### Tool : gds2rh
### RedHawk Version : 19.1.7p1 RHEL6
### Vendor : Apache Design, Inc. A Subsidiary of ANSYS, Inc. 
### Date : Mar 02 2019, 00:03:14 

### Date generated : Wed Sep 14 16:23:46 2022
 
### Command : gds2rh /nfs/an/disks/an_mos_scratch01/mos/prod/runs/c224uhdlpsprf-ext-version-r1-0-1/r641701_00_00/r641701_00_00/avm/rv_avm/gds2rh_options_powerup.txt

VERSION 5.5 ;
NAMESCASESENSITIVE ON ;
DIVIDERCHAR "/" ;
BUSBITCHARS "[]" ;
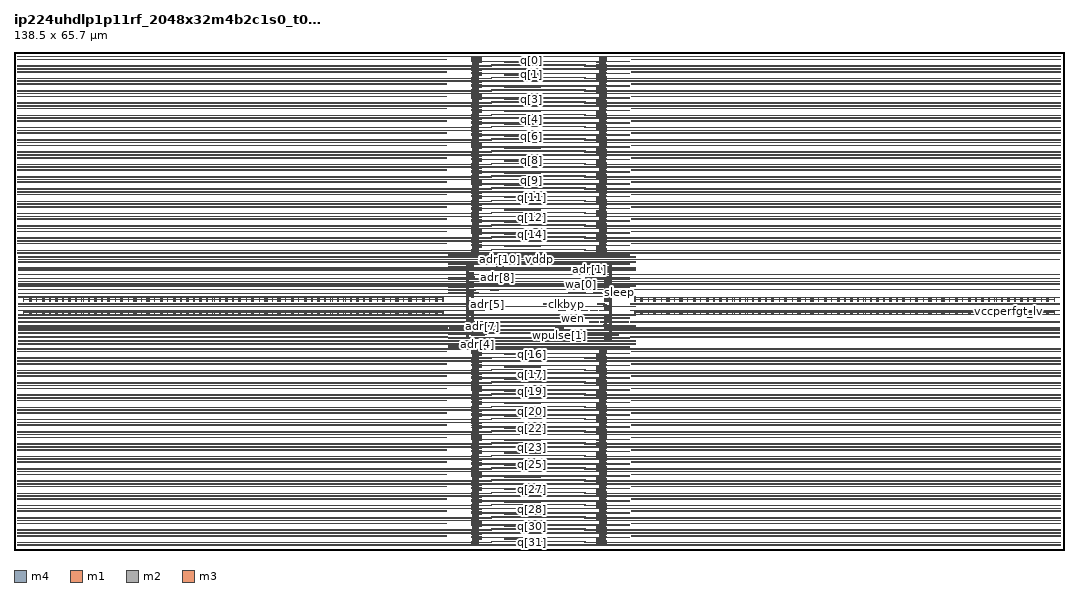
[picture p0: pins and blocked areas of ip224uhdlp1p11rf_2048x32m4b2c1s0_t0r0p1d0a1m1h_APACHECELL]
MACRO ip224uhdlp1p11rf_2048x32m4b2c1s0_t0r0p1d0a1m1h_APACHECELL
 ORIGIN 0.000000 0.000000 ;
 SIZE 138.500000 BY 65.700000 ;
 PIN adr[0]
 DIRECTION INPUT ;
 USE SIGNAL ;
 PORT
 LAYER m4 ;
 RECT 75.807500 37.004000 76.997500 37.080000 ;
 END
 END adr[0]
 PIN adr[10]
 DIRECTION INPUT ;
 USE SIGNAL ;
 PORT
 LAYER m4 ;
 RECT 63.625500 37.300000 64.577000 37.376000 ;
 END
 END adr[10]
 PIN adr[1]
 DIRECTION INPUT ;
 USE SIGNAL ;
 PORT
 LAYER m4 ;
 RECT 75.412500 35.884000 76.399500 35.960000 ;
 END
 END adr[1]
 PIN adr[2]
 DIRECTION INPUT ;
 USE SIGNAL ;
 PORT
 LAYER m4 ;
 RECT 75.238000 34.928000 76.412000 35.004000 ;
 END
 END adr[2]
 PIN adr[3]
 DIRECTION INPUT ;
 USE SIGNAL ;
 PORT
 LAYER m4 ;
 RECT 76.492000 34.928000 77.654000 35.004000 ;
 END
 END adr[3]
 PIN adr[4]
 DIRECTION INPUT ;
 USE SIGNAL ;
 PORT
 LAYER m4 ;
 RECT 60.693000 27.040000 61.650000 27.116000 ;
 END
 END adr[4]
 PIN adr[5]
 DIRECTION INPUT ;
 USE SIGNAL ;
 PORT
 LAYER m4 ;
 RECT 61.974500 32.406000 62.914000 32.462000 ;
 END
 END adr[5]
 PIN adr[6]
 DIRECTION INPUT ;
 USE SIGNAL ;
 PORT
 LAYER m4 ;
 RECT 60.656000 28.306000 62.037000 28.382000 ;
 END
 END adr[6]
 PIN adr[7]
 DIRECTION INPUT ;
 USE SIGNAL ;
 PORT
 LAYER m4 ;
 RECT 61.080500 28.456000 62.389000 28.532000 ;
 END
 END adr[7]
 PIN adr[8]
 DIRECTION INPUT ;
 USE SIGNAL ;
 PORT
 LAYER m4 ;
 RECT 63.343000 35.884000 64.267500 35.960000 ;
 END
 END adr[8]
 PIN adr[9]
 DIRECTION INPUT ;
 USE SIGNAL ;
 PORT
 LAYER m4 ;
 RECT 63.355000 37.004000 64.485000 37.080000 ;
 END
 END adr[9]
 PIN bc1
 DIRECTION INPUT ;
 USE SIGNAL ;
 PORT
 LAYER m4 ;
 RECT 75.492500 35.620000 76.556500 35.696000 ;
 END
 END bc1
 PIN bc2
 DIRECTION INPUT ;
 USE SIGNAL ;
 PORT
 LAYER m4 ;
 RECT 76.412000 33.938000 77.551500 33.994000 ;
 END
 END bc2
 PIN clkbyp
 DIRECTION INPUT ;
 USE SIGNAL ;
 PORT
 LAYER m4 ;
 RECT 72.415000 32.406000 73.267500 32.462000 ;
 END
 END clkbyp
 PIN deepslp
 DIRECTION INPUT ;
 USE SIGNAL ;
 PORT
 LAYER m4 ;
 RECT 76.916000 32.406000 77.910000 32.462000 ;
 END
 END deepslp
 PIN din[0]
 DIRECTION INPUT ;
 USE SIGNAL ;
 PORT
 LAYER m4 ;
 RECT 64.658000 64.268000 67.152500 64.376000 ;
 END
 END din[0]
 PIN din[10]
 DIRECTION INPUT ;
 USE SIGNAL ;
 PORT
 LAYER m4 ;
 RECT 64.658000 48.068000 67.152500 48.176000 ;
 END
 END din[10]
 PIN din[11]
 DIRECTION INPUT ;
 USE SIGNAL ;
 PORT
 LAYER m4 ;
 RECT 64.658000 46.448000 67.152500 46.556000 ;
 END
 END din[11]
 PIN din[12]
 DIRECTION INPUT ;
 USE SIGNAL ;
 PORT
 LAYER m4 ;
 RECT 64.658000 44.828000 67.152500 44.936000 ;
 END
 END din[12]
 PIN din[13]
 DIRECTION INPUT ;
 USE SIGNAL ;
 PORT
 LAYER m4 ;
 RECT 64.658000 43.208000 67.152500 43.316000 ;
 END
 END din[13]
 PIN din[14]
 DIRECTION INPUT ;
 USE SIGNAL ;
 PORT
 LAYER m4 ;
 RECT 64.658000 41.588000 67.152500 41.696000 ;
 END
 END din[14]
 PIN din[15]
 DIRECTION INPUT ;
 USE SIGNAL ;
 PORT
 LAYER m4 ;
 RECT 64.658000 39.968000 67.152500 40.076000 ;
 END
 END din[15]
 PIN din[16]
 DIRECTION INPUT ;
 USE SIGNAL ;
 PORT
 LAYER m4 ;
 RECT 64.658000 25.748000 67.152500 25.856000 ;
 END
 END din[16]
 PIN din[17]
 DIRECTION INPUT ;
 USE SIGNAL ;
 PORT
 LAYER m4 ;
 RECT 64.658000 24.128000 67.152500 24.236000 ;
 END
 END din[17]
 PIN din[18]
 DIRECTION INPUT ;
 USE SIGNAL ;
 PORT
 LAYER m4 ;
 RECT 64.658000 22.508000 67.152500 22.616000 ;
 END
 END din[18]
 PIN din[19]
 DIRECTION INPUT ;
 USE SIGNAL ;
 PORT
 LAYER m4 ;
 RECT 64.658000 20.888000 67.152500 20.996000 ;
 END
 END din[19]
 PIN din[1]
 DIRECTION INPUT ;
 USE SIGNAL ;
 PORT
 LAYER m4 ;
 RECT 64.658000 62.648000 67.152500 62.756000 ;
 END
 END din[1]
 PIN din[20]
 DIRECTION INPUT ;
 USE SIGNAL ;
 PORT
 LAYER m4 ;
 RECT 64.658000 19.268000 67.152500 19.376000 ;
 END
 END din[20]
 PIN din[21]
 DIRECTION INPUT ;
 USE SIGNAL ;
 PORT
 LAYER m4 ;
 RECT 64.658000 17.648000 67.152500 17.756000 ;
 END
 END din[21]
 PIN din[22]
 DIRECTION INPUT ;
 USE SIGNAL ;
 PORT
 LAYER m4 ;
 RECT 64.658000 16.028000 67.152500 16.136000 ;
 END
 END din[22]
 PIN din[23]
 DIRECTION INPUT ;
 USE SIGNAL ;
 PORT
 LAYER m4 ;
 RECT 64.658000 14.408000 67.152500 14.516000 ;
 END
 END din[23]
 PIN din[24]
 DIRECTION INPUT ;
 USE SIGNAL ;
 PORT
 LAYER m4 ;
 RECT 64.658000 12.788000 67.152500 12.896000 ;
 END
 END din[24]
 PIN din[25]
 DIRECTION INPUT ;
 USE SIGNAL ;
 PORT
 LAYER m4 ;
 RECT 64.658000 11.168000 67.152500 11.276000 ;
 END
 END din[25]
 PIN din[26]
 DIRECTION INPUT ;
 USE SIGNAL ;
 PORT
 LAYER m4 ;
 RECT 64.658000 9.548000 67.152500 9.656000 ;
 END
 END din[26]
 PIN din[27]
 DIRECTION INPUT ;
 USE SIGNAL ;
 PORT
 LAYER m4 ;
 RECT 64.658000 7.928000 67.152500 8.036000 ;
 END
 END din[27]
 PIN din[28]
 DIRECTION INPUT ;
 USE SIGNAL ;
 PORT
 LAYER m4 ;
 RECT 64.658000 6.308000 67.152500 6.416000 ;
 END
 END din[28]
 PIN din[29]
 DIRECTION INPUT ;
 USE SIGNAL ;
 PORT
 LAYER m4 ;
 RECT 64.658000 4.688000 67.152500 4.796000 ;
 END
 END din[29]
 PIN din[2]
 DIRECTION INPUT ;
 USE SIGNAL ;
 PORT
 LAYER m4 ;
 RECT 64.658000 61.028000 67.152500 61.136000 ;
 END
 END din[2]
 PIN din[30]
 DIRECTION INPUT ;
 USE SIGNAL ;
 PORT
 LAYER m4 ;
 RECT 64.658000 3.068000 67.152500 3.176000 ;
 END
 END din[30]
 PIN din[31]
 DIRECTION INPUT ;
 USE SIGNAL ;
 PORT
 LAYER m4 ;
 RECT 64.658000 1.448000 67.152500 1.556000 ;
 END
 END din[31]
 PIN din[3]
 DIRECTION INPUT ;
 USE SIGNAL ;
 PORT
 LAYER m4 ;
 RECT 64.658000 59.408000 67.152500 59.516000 ;
 END
 END din[3]
 PIN din[4]
 DIRECTION INPUT ;
 USE SIGNAL ;
 PORT
 LAYER m4 ;
 RECT 64.658000 57.788000 67.152500 57.896000 ;
 END
 END din[4]
 PIN din[5]
 DIRECTION INPUT ;
 USE SIGNAL ;
 PORT
 LAYER m4 ;
 RECT 64.658000 56.168000 67.152500 56.276000 ;
 END
 END din[5]
 PIN din[6]
 DIRECTION INPUT ;
 USE SIGNAL ;
 PORT
 LAYER m4 ;
 RECT 64.658000 54.548000 67.152500 54.656000 ;
 END
 END din[6]
 PIN din[7]
 DIRECTION INPUT ;
 USE SIGNAL ;
 PORT
 LAYER m4 ;
 RECT 64.658000 52.928000 67.152500 53.036000 ;
 END
 END din[7]
 PIN din[8]
 DIRECTION INPUT ;
 USE SIGNAL ;
 PORT
 LAYER m4 ;
 RECT 64.658000 51.308000 67.152500 51.416000 ;
 END
 END din[8]
 PIN din[9]
 DIRECTION INPUT ;
 USE SIGNAL ;
 PORT
 LAYER m4 ;
 RECT 64.658000 49.688000 67.152500 49.796000 ;
 END
 END din[9]
 PIN fwen
 DIRECTION INPUT ;
 USE SIGNAL ;
 PORT
 LAYER m4 ;
 RECT 76.067500 31.570000 77.022000 31.626000 ;
 END
 END fwen
 PIN mc[0]
 DIRECTION INPUT ;
 USE SIGNAL ;
 PORT
 LAYER m4 ;
 RECT 62.892000 34.204000 63.931000 34.280000 ;
 END
 END mc[0]
 PIN mc[1]
 DIRECTION INPUT ;
 USE SIGNAL ;
 PORT
 LAYER m4 ;
 RECT 60.672000 35.620000 61.900000 35.696000 ;
 END
 END mc[1]
 PIN mc[2]
 DIRECTION INPUT ;
 USE SIGNAL ;
 PORT
 LAYER m4 ;
 RECT 62.031000 35.620000 63.173000 35.696000 ;
 END
 END mc[2]
 PIN mcen
 DIRECTION INPUT ;
 USE SIGNAL ;
 PORT
 LAYER m4 ;
 RECT 62.128500 35.884000 63.065000 35.960000 ;
 END
 END mcen
 PIN mpr
 DIRECTION OUTPUT ;
 USE SIGNAL ;
 PORT
 LAYER m4 ;
 RECT 74.773000 31.570000 75.709000 31.626000 ;
 END
 END mpr
 PIN q[0]
 DIRECTION OUTPUT ;
 USE SIGNAL ;
 PORT
 LAYER m4 ;
 RECT 67.232500 64.268000 69.386500 64.376000 ;
 END
 END q[0]
 PIN q[10]
 DIRECTION OUTPUT ;
 USE SIGNAL ;
 PORT
 LAYER m4 ;
 RECT 67.232500 48.068000 69.386500 48.176000 ;
 END
 END q[10]
 PIN q[11]
 DIRECTION OUTPUT ;
 USE SIGNAL ;
 PORT
 LAYER m4 ;
 RECT 67.232500 46.448000 69.386500 46.556000 ;
 END
 END q[11]
 PIN q[12]
 DIRECTION OUTPUT ;
 USE SIGNAL ;
 PORT
 LAYER m4 ;
 RECT 67.232500 44.828000 69.386500 44.936000 ;
 END
 END q[12]
 PIN q[13]
 DIRECTION OUTPUT ;
 USE SIGNAL ;
 PORT
 LAYER m4 ;
 RECT 67.232500 43.208000 69.386500 43.316000 ;
 END
 END q[13]
 PIN q[14]
 DIRECTION OUTPUT ;
 USE SIGNAL ;
 PORT
 LAYER m4 ;
 RECT 67.232500 41.588000 69.386500 41.696000 ;
 END
 END q[14]
 PIN q[15]
 DIRECTION OUTPUT ;
 USE SIGNAL ;
 PORT
 LAYER m4 ;
 RECT 67.232500 39.968000 69.386500 40.076000 ;
 END
 END q[15]
 PIN q[16]
 DIRECTION OUTPUT ;
 USE SIGNAL ;
 PORT
 LAYER m4 ;
 RECT 67.232500 25.748000 69.386500 25.856000 ;
 END
 END q[16]
 PIN q[17]
 DIRECTION OUTPUT ;
 USE SIGNAL ;
 PORT
 LAYER m4 ;
 RECT 67.232500 24.128000 69.386500 24.236000 ;
 END
 END q[17]
 PIN q[18]
 DIRECTION OUTPUT ;
 USE SIGNAL ;
 PORT
 LAYER m4 ;
 RECT 67.232500 22.508000 69.386500 22.616000 ;
 END
 END q[18]
 PIN q[19]
 DIRECTION OUTPUT ;
 USE SIGNAL ;
 PORT
 LAYER m4 ;
 RECT 67.232500 20.888000 69.386500 20.996000 ;
 END
 END q[19]
 PIN q[1]
 DIRECTION OUTPUT ;
 USE SIGNAL ;
 PORT
 LAYER m4 ;
 RECT 67.232500 62.648000 69.386500 62.756000 ;
 END
 END q[1]
 PIN q[20]
 DIRECTION OUTPUT ;
 USE SIGNAL ;
 PORT
 LAYER m4 ;
 RECT 67.232500 19.268000 69.386500 19.376000 ;
 END
 END q[20]
 PIN q[21]
 DIRECTION OUTPUT ;
 USE SIGNAL ;
 PORT
 LAYER m4 ;
 RECT 67.232500 17.648000 69.386500 17.756000 ;
 END
 END q[21]
 PIN q[22]
 DIRECTION OUTPUT ;
 USE SIGNAL ;
 PORT
 LAYER m4 ;
 RECT 67.232500 16.028000 69.386500 16.136000 ;
 END
 END q[22]
 PIN q[23]
 DIRECTION OUTPUT ;
 USE SIGNAL ;
 PORT
 LAYER m4 ;
 RECT 67.232500 14.408000 69.386500 14.516000 ;
 END
 END q[23]
 PIN q[24]
 DIRECTION OUTPUT ;
 USE SIGNAL ;
 PORT
 LAYER m4 ;
 RECT 67.232500 12.788000 69.386500 12.896000 ;
 END
 END q[24]
 PIN q[25]
 DIRECTION OUTPUT ;
 USE SIGNAL ;
 PORT
 LAYER m4 ;
 RECT 67.232500 11.168000 69.386500 11.276000 ;
 END
 END q[25]
 PIN q[26]
 DIRECTION OUTPUT ;
 USE SIGNAL ;
 PORT
 LAYER m4 ;
 RECT 67.232500 9.548000 69.386500 9.656000 ;
 END
 END q[26]
 PIN q[27]
 DIRECTION OUTPUT ;
 USE SIGNAL ;
 PORT
 LAYER m4 ;
 RECT 67.232500 7.928000 69.386500 8.036000 ;
 END
 END q[27]
 PIN q[28]
 DIRECTION OUTPUT ;
 USE SIGNAL ;
 PORT
 LAYER m4 ;
 RECT 67.232500 6.308000 69.386500 6.416000 ;
 END
 END q[28]
 PIN q[29]
 DIRECTION OUTPUT ;
 USE SIGNAL ;
 PORT
 LAYER m4 ;
 RECT 67.232500 4.688000 69.386500 4.796000 ;
 END
 END q[29]
 PIN q[2]
 DIRECTION OUTPUT ;
 USE SIGNAL ;
 PORT
 LAYER m4 ;
 RECT 67.232500 61.028000 69.386500 61.136000 ;
 END
 END q[2]
 PIN q[30]
 DIRECTION OUTPUT ;
 USE SIGNAL ;
 PORT
 LAYER m4 ;
 RECT 67.232500 3.068000 69.386500 3.176000 ;
 END
 END q[30]
 PIN q[31]
 DIRECTION OUTPUT ;
 USE SIGNAL ;
 PORT
 LAYER m4 ;
 RECT 67.232500 1.448000 69.386500 1.556000 ;
 END
 END q[31]
 PIN q[3]
 DIRECTION OUTPUT ;
 USE SIGNAL ;
 PORT
 LAYER m4 ;
 RECT 67.232500 59.408000 69.386500 59.516000 ;
 END
 END q[3]
 PIN q[4]
 DIRECTION OUTPUT ;
 USE SIGNAL ;
 PORT
 LAYER m4 ;
 RECT 67.232500 57.788000 69.386500 57.896000 ;
 END
 END q[4]
 PIN q[5]
 DIRECTION OUTPUT ;
 USE SIGNAL ;
 PORT
 LAYER m4 ;
 RECT 67.232500 56.168000 69.386500 56.276000 ;
 END
 END q[5]
 PIN q[6]
 DIRECTION OUTPUT ;
 USE SIGNAL ;
 PORT
 LAYER m4 ;
 RECT 67.232500 54.548000 69.386500 54.656000 ;
 END
 END q[6]
 PIN q[7]
 DIRECTION OUTPUT ;
 USE SIGNAL ;
 PORT
 LAYER m4 ;
 RECT 67.232500 52.928000 69.386500 53.036000 ;
 END
 END q[7]
 PIN q[8]
 DIRECTION OUTPUT ;
 USE SIGNAL ;
 PORT
 LAYER m4 ;
 RECT 67.232500 51.308000 69.386500 51.416000 ;
 END
 END q[8]
 PIN q[9]
 DIRECTION OUTPUT ;
 USE SIGNAL ;
 PORT
 LAYER m4 ;
 RECT 67.232500 49.688000 69.386500 49.796000 ;
 END
 END q[9]
 PIN ren
 DIRECTION INPUT ;
 USE SIGNAL ;
 PORT
 LAYER m4 ;
 RECT 71.798000 31.570000 72.703500 31.626000 ;
 END
 END ren
 PIN shutoff
 DIRECTION INPUT ;
 USE SIGNAL ;
 PORT
 LAYER m4 ;
 RECT 77.244000 31.570000 78.165500 31.626000 ;
 END
 END shutoff
 PIN sleep
 DIRECTION INPUT ;
 USE SIGNAL ;
 PORT
 LAYER m4 ;
 RECT 79.403500 33.938000 80.326500 33.994000 ;
 END
 END sleep
 PIN wa[0]
 DIRECTION INPUT ;
 USE SIGNAL ;
 PORT
 LAYER m4 ;
 RECT 74.360000 33.938000 75.324500 33.994000 ;
 END
 END wa[0]
 PIN wa[1]
 DIRECTION INPUT ;
 USE SIGNAL ;
 PORT
 LAYER m4 ;
 RECT 73.147500 33.938000 74.178000 33.994000 ;
 END
 END wa[1]
 PIN wen
 DIRECTION INPUT ;
 USE SIGNAL ;
 PORT
 LAYER m4 ;
 RECT 73.262000 31.570000 74.150000 31.626000 ;
 END
 END wen
 PIN wpulse[0]
 DIRECTION INPUT ;
 USE SIGNAL ;
 PORT
 LAYER m4 ;
 RECT 75.887000 30.004000 77.144000 30.080000 ;
 END
 END wpulse[0]
 PIN wpulse[1]
 DIRECTION INPUT ;
 USE SIGNAL ;
 PORT
 LAYER m4 ;
 RECT 71.406500 29.280000 72.450000 29.356000 ;
 END
 END wpulse[1]
 PIN wpulseen
 DIRECTION INPUT ;
 USE SIGNAL ;
 PORT
 LAYER m4 ;
 RECT 72.212500 30.004000 73.099000 30.080000 ;
 END
 END wpulseen
 PIN clk
 DIRECTION INPUT ;
 USE CLOCK ;
 PORT
 LAYER m4 ;
 RECT 69.872500 32.406000 70.904500 32.462000 ;
 END
 END clk
 PIN vddp
 DIRECTION INPUT ;
 USE POWER ;
 PORT
 LAYER m4 ;
 RECT 0.480000 0.958000 63.049000 1.034000 ;
 RECT 0.480000 1.846000 57.036000 1.922000 ;
 RECT 0.480000 10.678000 63.049000 10.754000 ;
 RECT 0.480000 11.566000 57.036000 11.642000 ;
 RECT 0.480000 12.298000 63.049000 12.374000 ;
 RECT 0.480000 13.186000 57.036000 13.262000 ;
 RECT 0.480000 13.918000 63.049000 13.994000 ;
 RECT 0.480000 14.806000 57.036000 14.882000 ;
 RECT 0.480000 15.538000 63.049000 15.614000 ;
 RECT 0.480000 16.426000 57.036000 16.502000 ;
 RECT 0.480000 17.158000 63.049000 17.234000 ;
 RECT 0.480000 18.046000 57.036000 18.122000 ;
 RECT 0.480000 18.778000 63.049000 18.854000 ;
 RECT 0.480000 19.666000 57.036000 19.742000 ;
 RECT 0.480000 2.578000 63.049000 2.654000 ;
 RECT 0.480000 20.398000 63.049000 20.474000 ;
 RECT 0.480000 21.286000 57.036000 21.362000 ;
 RECT 0.480000 22.018000 63.049000 22.094000 ;
 RECT 0.480000 22.906000 57.036000 22.982000 ;
 RECT 0.480000 23.638000 63.049000 23.714000 ;
 RECT 0.480000 24.526000 57.036000 24.602000 ;
 RECT 0.480000 25.258000 63.049000 25.334000 ;
 RECT 0.480000 26.146000 57.036000 26.222000 ;
 RECT 0.480000 3.466000 57.036000 3.542000 ;
 RECT 0.480000 39.478000 63.049000 39.554000 ;
 RECT 0.480000 4.198000 63.049000 4.274000 ;
 RECT 0.480000 40.366000 57.036000 40.442000 ;
 RECT 0.480000 41.098000 63.049000 41.174000 ;
 RECT 0.480000 41.986000 57.036000 42.062000 ;
 RECT 0.480000 42.718000 63.049000 42.794000 ;
 RECT 0.480000 43.606000 57.036000 43.682000 ;
 RECT 0.480000 44.338000 63.049000 44.414000 ;
 RECT 0.480000 45.226000 57.036000 45.302000 ;
 RECT 0.480000 45.958000 63.049000 46.034000 ;
 RECT 0.480000 46.846000 57.036000 46.922000 ;
 RECT 0.480000 47.578000 63.049000 47.654000 ;
 RECT 0.480000 48.466000 57.036000 48.542000 ;
 RECT 0.480000 49.198000 63.049000 49.274000 ;
 RECT 0.480000 5.086000 57.036000 5.162000 ;
 RECT 0.480000 5.818000 63.049000 5.894000 ;
 RECT 0.480000 50.086000 57.036000 50.162000 ;
 RECT 0.480000 50.818000 63.049000 50.894000 ;
 RECT 0.480000 51.706000 57.036000 51.782000 ;
 RECT 0.480000 52.438000 63.049000 52.514000 ;
 RECT 0.480000 53.326000 57.036000 53.402000 ;
 RECT 0.480000 54.058000 63.049000 54.134000 ;
 RECT 0.480000 54.946000 57.036000 55.022000 ;
 RECT 0.480000 55.678000 63.049000 55.754000 ;
 RECT 0.480000 56.566000 57.036000 56.642000 ;
 RECT 0.480000 57.298000 63.049000 57.374000 ;
 RECT 0.480000 58.186000 57.036000 58.262000 ;
 RECT 0.480000 58.918000 63.049000 58.994000 ;
 RECT 0.480000 59.806000 57.036000 59.882000 ;
 RECT 0.480000 6.706000 57.036000 6.782000 ;
 RECT 0.480000 60.538000 63.049000 60.614000 ;
 RECT 0.480000 61.426000 57.036000 61.502000 ;
 RECT 0.480000 62.158000 63.049000 62.234000 ;
 RECT 0.480000 63.046000 57.036000 63.122000 ;
 RECT 0.480000 63.778000 63.049000 63.854000 ;
 RECT 0.480000 64.666000 57.036000 64.742000 ;
 RECT 0.480000 7.438000 63.049000 7.514000 ;
 RECT 0.480000 8.326000 57.036000 8.402000 ;
 RECT 0.480000 9.058000 63.049000 9.134000 ;
 RECT 0.480000 9.946000 57.036000 10.022000 ;
 RECT 0.616000 28.028000 57.208000 28.104000 ;
 RECT 0.616000 28.588000 137.884000 28.664000 ;
 RECT 0.616000 28.984000 137.884000 29.060000 ;
 RECT 0.616000 29.280000 57.208000 29.356000 ;
 RECT 0.616000 30.004000 57.208000 30.080000 ;
 RECT 0.616000 31.072000 56.560000 31.116000 ;
 RECT 0.616000 31.570000 57.208000 31.626000 ;
 RECT 0.616000 32.406000 57.208000 32.462000 ;
 RECT 0.616000 33.324000 56.560000 33.368000 ;
 RECT 0.616000 34.336000 137.884000 34.412000 ;
 RECT 0.616000 35.060000 137.884000 35.136000 ;
 RECT 0.616000 35.356000 137.884000 35.432000 ;
 RECT 0.616000 35.752000 137.884000 35.828000 ;
 RECT 0.616000 36.312000 137.884000 36.388000 ;
 RECT 0.616000 38.256000 137.884000 38.364000 ;
 RECT 57.248000 26.644000 81.252000 26.720000 ;
 RECT 57.248000 26.776000 81.252000 26.852000 ;
 RECT 57.248000 27.040000 60.613000 27.116000 ;
 RECT 57.248000 27.896000 81.252000 27.972000 ;
 RECT 57.248000 28.456000 61.000500 28.532000 ;
 RECT 57.248000 37.696000 81.252000 37.772000 ;
 RECT 57.248000 38.716000 81.252000 38.792000 ;
 RECT 57.248000 38.980000 81.252000 39.056000 ;
 RECT 57.256500 33.938000 61.250500 33.994000 ;
 RECT 57.256500 34.204000 60.816500 34.280000 ;
 RECT 57.256500 34.632000 60.566500 34.708000 ;
 RECT 57.256500 35.620000 60.566500 35.696000 ;
 RECT 57.256500 35.884000 60.566500 35.960000 ;
 RECT 57.256500 37.004000 60.566500 37.080000 ;
 RECT 57.256500 37.300000 60.566500 37.376000 ;
 RECT 57.299000 32.406000 61.749500 32.462000 ;
 RECT 57.302000 31.570000 62.013500 31.626000 ;
 RECT 57.317000 30.004000 72.132500 30.080000 ;
 RECT 57.380000 29.280000 61.212000 29.356000 ;
 RECT 62.973000 1.080000 75.329500 1.156000 ;
 RECT 62.973000 10.800000 75.329500 10.876000 ;
 RECT 62.973000 12.420000 75.329500 12.496000 ;
 RECT 62.973000 14.040000 75.329500 14.116000 ;
 RECT 62.973000 15.660000 75.329500 15.736000 ;
 RECT 62.973000 17.280000 75.329500 17.356000 ;
 RECT 62.973000 18.900000 75.329500 18.976000 ;
 RECT 62.973000 2.700000 75.329500 2.776000 ;
 RECT 62.973000 20.520000 75.329500 20.596000 ;
 RECT 62.973000 22.140000 75.329500 22.216000 ;
 RECT 62.973000 23.760000 75.329500 23.836000 ;
 RECT 62.973000 25.380000 75.329500 25.456000 ;
 RECT 62.973000 39.600000 75.329500 39.676000 ;
 RECT 62.973000 4.320000 75.329500 4.396000 ;
 RECT 62.973000 41.220000 75.329500 41.296000 ;
 RECT 62.973000 42.840000 75.329500 42.916000 ;
 RECT 62.973000 44.460000 75.329500 44.536000 ;
 RECT 62.973000 46.080000 75.329500 46.156000 ;
 RECT 62.973000 47.700000 75.329500 47.776000 ;
 RECT 62.973000 49.320000 75.329500 49.396000 ;
 RECT 62.973000 5.940000 75.329500 6.016000 ;
 RECT 62.973000 50.940000 75.329500 51.016000 ;
 RECT 62.973000 52.560000 75.329500 52.636000 ;
 RECT 62.973000 54.180000 75.329500 54.256000 ;
 RECT 62.973000 55.800000 75.329500 55.876000 ;
 RECT 62.973000 57.420000 75.329500 57.496000 ;
 RECT 62.973000 59.040000 75.329500 59.116000 ;
 RECT 62.973000 60.660000 75.329500 60.736000 ;
 RECT 62.973000 62.280000 75.329500 62.356000 ;
 RECT 62.973000 63.900000 75.329500 63.976000 ;
 RECT 62.973000 7.560000 75.329500 7.636000 ;
 RECT 62.973000 9.180000 75.329500 9.256000 ;
 RECT 73.686000 34.632000 81.205500 34.688000 ;
 RECT 75.253500 0.958000 138.020000 1.034000 ;
 RECT 75.253500 10.678000 138.020000 10.754000 ;
 RECT 75.253500 12.298000 138.020000 12.374000 ;
 RECT 75.253500 13.918000 138.020000 13.994000 ;
 RECT 75.253500 15.538000 138.020000 15.614000 ;
 RECT 75.253500 17.158000 138.020000 17.234000 ;
 RECT 75.253500 18.778000 138.020000 18.854000 ;
 RECT 75.253500 2.578000 138.020000 2.654000 ;
 RECT 75.253500 20.398000 138.020000 20.474000 ;
 RECT 75.253500 22.018000 138.020000 22.094000 ;
 RECT 75.253500 23.638000 138.020000 23.714000 ;
 RECT 75.253500 25.258000 138.020000 25.334000 ;
 RECT 75.253500 39.478000 138.020000 39.554000 ;
 RECT 75.253500 4.198000 138.020000 4.274000 ;
 RECT 75.253500 41.098000 138.020000 41.174000 ;
 RECT 75.253500 42.718000 138.020000 42.794000 ;
 RECT 75.253500 44.338000 138.020000 44.414000 ;
 RECT 75.253500 45.958000 138.020000 46.034000 ;
 RECT 75.253500 47.578000 138.020000 47.654000 ;
 RECT 75.253500 49.198000 138.020000 49.274000 ;
 RECT 75.253500 5.818000 138.020000 5.894000 ;
 RECT 75.253500 50.818000 138.020000 50.894000 ;
 RECT 75.253500 52.438000 138.020000 52.514000 ;
 RECT 75.253500 54.058000 138.020000 54.134000 ;
 RECT 75.253500 55.678000 138.020000 55.754000 ;
 RECT 75.253500 57.298000 138.020000 57.374000 ;
 RECT 75.253500 58.918000 138.020000 58.994000 ;
 RECT 75.253500 60.538000 138.020000 60.614000 ;
 RECT 75.253500 62.158000 138.020000 62.234000 ;
 RECT 75.253500 63.778000 138.020000 63.854000 ;
 RECT 75.253500 7.438000 138.020000 7.514000 ;
 RECT 75.253500 9.058000 138.020000 9.134000 ;
 RECT 75.631000 28.292000 79.740000 28.400000 ;
 RECT 76.479500 35.884000 81.252000 35.960000 ;
 RECT 76.636500 35.620000 81.252000 35.696000 ;
 RECT 77.077500 37.004000 81.252000 37.080000 ;
 RECT 77.334500 30.004000 81.112500 30.080000 ;
 RECT 77.859000 29.280000 81.252000 29.356000 ;
 RECT 78.017500 34.928000 81.252500 35.004000 ;
 RECT 81.292000 28.028000 137.884000 28.104000 ;
 RECT 81.292000 30.004000 137.884000 30.080000 ;
 RECT 81.292000 31.570000 137.884000 31.626000 ;
 RECT 81.292000 32.406000 137.884000 32.462000 ;
 RECT 81.332000 29.280000 137.884000 29.356000 ;
 RECT 81.397000 1.846000 138.020000 1.922000 ;
 RECT 81.397000 11.566000 138.020000 11.642000 ;
 RECT 81.397000 13.186000 138.020000 13.262000 ;
 RECT 81.397000 14.806000 138.020000 14.882000 ;
 RECT 81.397000 16.426000 138.020000 16.502000 ;
 RECT 81.397000 18.046000 138.020000 18.122000 ;
 RECT 81.397000 19.666000 138.020000 19.742000 ;
 RECT 81.397000 21.286000 138.020000 21.362000 ;
 RECT 81.397000 22.906000 138.020000 22.982000 ;
 RECT 81.397000 24.526000 138.020000 24.602000 ;
 RECT 81.397000 26.146000 138.020000 26.222000 ;
 RECT 81.397000 3.466000 138.020000 3.542000 ;
 RECT 81.397000 40.366000 138.020000 40.442000 ;
 RECT 81.397000 41.986000 138.020000 42.062000 ;
 RECT 81.397000 43.606000 138.020000 43.682000 ;
 RECT 81.397000 45.226000 138.020000 45.302000 ;
 RECT 81.397000 46.846000 138.020000 46.922000 ;
 RECT 81.397000 48.466000 138.020000 48.542000 ;
 RECT 81.397000 5.086000 138.020000 5.162000 ;
 RECT 81.397000 50.086000 138.020000 50.162000 ;
 RECT 81.397000 51.706000 138.020000 51.782000 ;
 RECT 81.397000 53.326000 138.020000 53.402000 ;
 RECT 81.397000 54.946000 138.020000 55.022000 ;
 RECT 81.397000 56.566000 138.020000 56.642000 ;
 RECT 81.397000 58.186000 138.020000 58.262000 ;
 RECT 81.397000 59.806000 138.020000 59.882000 ;
 RECT 81.397000 6.706000 138.020000 6.782000 ;
 RECT 81.397000 61.426000 138.020000 61.502000 ;
 RECT 81.397000 63.046000 138.020000 63.122000 ;
 RECT 81.397000 64.666000 138.020000 64.742000 ;
 RECT 81.397000 8.326000 138.020000 8.402000 ;
 RECT 81.397000 9.946000 138.020000 10.022000 ;
 RECT 81.940000 31.072000 137.884000 31.116000 ;
 RECT 81.940000 33.324000 137.884000 33.368000 ;
 END
 END vddp
 PIN vss
 DIRECTION INOUT ;
 USE GROUND ;
 PORT
 LAYER m4 ;
 RECT 0.480000 0.592000 138.020000 0.668000 ;
 RECT 0.480000 10.312000 138.020000 10.388000 ;
 RECT 0.480000 11.932000 138.020000 12.008000 ;
 RECT 0.480000 13.552000 138.020000 13.628000 ;
 RECT 0.480000 15.172000 138.020000 15.248000 ;
 RECT 0.480000 16.792000 138.020000 16.868000 ;
 RECT 0.480000 18.412000 138.020000 18.488000 ;
 RECT 0.480000 2.212000 138.020000 2.288000 ;
 RECT 0.480000 20.032000 138.020000 20.108000 ;
 RECT 0.480000 21.652000 138.020000 21.728000 ;
 RECT 0.480000 23.272000 138.020000 23.348000 ;
 RECT 0.480000 24.892000 138.020000 24.968000 ;
 RECT 0.480000 26.512000 138.020000 26.588000 ;
 RECT 0.480000 3.832000 138.020000 3.908000 ;
 RECT 0.480000 39.112000 138.020000 39.188000 ;
 RECT 0.480000 40.732000 138.020000 40.808000 ;
 RECT 0.480000 42.352000 138.020000 42.428000 ;
 RECT 0.480000 43.972000 138.020000 44.048000 ;
 RECT 0.480000 45.592000 138.020000 45.668000 ;
 RECT 0.480000 47.212000 138.020000 47.288000 ;
 RECT 0.480000 48.832000 138.020000 48.908000 ;
 RECT 0.480000 5.452000 138.020000 5.528000 ;
 RECT 0.480000 50.452000 138.020000 50.528000 ;
 RECT 0.480000 52.072000 138.020000 52.148000 ;
 RECT 0.480000 53.692000 138.020000 53.768000 ;
 RECT 0.480000 55.312000 138.020000 55.388000 ;
 RECT 0.480000 56.932000 138.020000 57.008000 ;
 RECT 0.480000 58.552000 138.020000 58.628000 ;
 RECT 0.480000 60.172000 138.020000 60.248000 ;
 RECT 0.480000 61.792000 138.020000 61.868000 ;
 RECT 0.480000 63.412000 138.020000 63.488000 ;
 RECT 0.480000 65.032000 138.020000 65.108000 ;
 RECT 0.480000 7.072000 138.020000 7.148000 ;
 RECT 0.480000 8.692000 138.020000 8.768000 ;
 RECT 0.616000 27.172000 81.940000 27.280000 ;
 RECT 0.616000 27.468000 81.940000 27.576000 ;
 RECT 0.616000 29.544000 81.940000 29.652000 ;
 RECT 0.616000 30.566000 57.208000 30.610000 ;
 RECT 0.616000 30.982000 81.940000 31.026000 ;
 RECT 0.616000 32.080000 81.940000 32.156000 ;
 RECT 0.616000 33.414000 81.940000 33.458000 ;
 RECT 0.616000 33.830000 57.208000 33.874000 ;
 RECT 0.616000 34.764000 81.940000 34.872000 ;
 RECT 0.616000 36.840000 81.940000 36.948000 ;
 RECT 0.616000 37.136000 81.940000 37.244000 ;
 RECT 0.616000 37.960000 81.940000 38.068000 ;
 RECT 0.616000 38.552000 81.940000 38.660000 ;
 RECT 57.335500 30.554000 81.127500 30.610000 ;
 RECT 57.366500 33.836000 81.211500 33.892000 ;
 RECT 60.461500 1.602000 81.215500 1.678000 ;
 RECT 60.461500 11.322000 81.215500 11.398000 ;
 RECT 60.461500 12.942000 81.215500 13.018000 ;
 RECT 60.461500 14.562000 81.215500 14.638000 ;
 RECT 60.461500 16.182000 81.215500 16.258000 ;
 RECT 60.461500 17.802000 81.215500 17.878000 ;
 RECT 60.461500 19.422000 81.215500 19.498000 ;
 RECT 60.461500 21.042000 81.215500 21.118000 ;
 RECT 60.461500 22.662000 81.215500 22.738000 ;
 RECT 60.461500 24.282000 81.215500 24.358000 ;
 RECT 60.461500 25.902000 81.215500 25.978000 ;
 RECT 60.461500 3.222000 81.215500 3.298000 ;
 RECT 60.461500 4.842000 81.215500 4.918000 ;
 RECT 60.461500 40.122000 81.215500 40.198000 ;
 RECT 60.461500 41.742000 81.215500 41.818000 ;
 RECT 60.461500 43.362000 81.215500 43.438000 ;
 RECT 60.461500 44.982000 81.215500 45.058000 ;
 RECT 60.461500 46.602000 81.215500 46.678000 ;
 RECT 60.461500 48.222000 81.215500 48.298000 ;
 RECT 60.461500 49.842000 81.215500 49.918000 ;
 RECT 60.461500 51.462000 81.215500 51.538000 ;
 RECT 60.461500 53.082000 81.215500 53.158000 ;
 RECT 60.461500 54.702000 81.215500 54.778000 ;
 RECT 60.461500 56.322000 81.215500 56.398000 ;
 RECT 60.461500 57.942000 81.215500 58.018000 ;
 RECT 60.461500 59.562000 81.215500 59.638000 ;
 RECT 60.461500 6.462000 81.215500 6.538000 ;
 RECT 60.461500 61.182000 81.215500 61.258000 ;
 RECT 60.461500 62.802000 81.215500 62.878000 ;
 RECT 60.461500 64.422000 81.215500 64.498000 ;
 RECT 60.461500 8.082000 81.215500 8.158000 ;
 RECT 60.461500 9.702000 81.215500 9.778000 ;
 END
 END vss
 PIN vccperfgt_lv
 DIRECTION INOUT ;
 USE POWER ;
 PORT
 LAYER m1 ;
 RECT 77.262000 13.658000 77.330000 14.512000 ;
 RECT 77.478000 13.658000 77.546000 14.512000 ;
 RECT 77.694000 13.658000 77.762000 15.142000 ;
 RECT 77.910000 13.658000 77.978000 15.142000 ;
 RECT 30.606000 31.117000 30.674000 31.635000 ;
 RECT 31.362000 31.163000 31.430000 31.657000 ;
 RECT 31.578000 31.163000 31.646000 31.657000 ;
 RECT 32.334000 31.117000 32.402000 31.635000 ;
 RECT 30.606000 32.805000 30.674000 33.323000 ;
 RECT 31.362000 32.783000 31.430000 33.277000 ;
 RECT 31.578000 32.783000 31.646000 33.277000 ;
 RECT 32.334000 32.805000 32.402000 33.323000 ;
 RECT 32.334000 31.117000 32.402000 31.635000 ;
 RECT 33.090000 31.163000 33.158000 31.657000 ;
 RECT 33.306000 31.163000 33.374000 31.657000 ;
 RECT 34.062000 31.117000 34.130000 31.635000 ;
 RECT 32.334000 32.805000 32.402000 33.323000 ;
 RECT 33.090000 32.783000 33.158000 33.277000 ;
 RECT 33.306000 32.783000 33.374000 33.277000 ;
 RECT 34.062000 32.805000 34.130000 33.323000 ;
 RECT 34.062000 31.117000 34.130000 31.635000 ;
 RECT 34.818000 31.163000 34.886000 31.657000 ;
 RECT 35.034000 31.163000 35.102000 31.657000 ;
 RECT 35.790000 31.117000 35.858000 31.635000 ;
 RECT 34.062000 32.805000 34.130000 33.323000 ;
 RECT 34.818000 32.783000 34.886000 33.277000 ;
 RECT 35.034000 32.783000 35.102000 33.277000 ;
 RECT 35.790000 32.805000 35.858000 33.323000 ;
 RECT 35.790000 31.117000 35.858000 31.635000 ;
 RECT 36.546000 31.163000 36.614000 31.657000 ;
 RECT 36.762000 31.163000 36.830000 31.657000 ;
 RECT 37.518000 31.117000 37.586000 31.635000 ;
 RECT 35.790000 32.805000 35.858000 33.323000 ;
 RECT 36.546000 32.783000 36.614000 33.277000 ;
 RECT 36.762000 32.783000 36.830000 33.277000 ;
 RECT 37.518000 32.805000 37.586000 33.323000 ;
 RECT 37.518000 31.117000 37.586000 31.635000 ;
 RECT 38.274000 31.163000 38.342000 31.657000 ;
 RECT 38.490000 31.163000 38.558000 31.657000 ;
 RECT 39.246000 31.117000 39.314000 31.635000 ;
 RECT 37.518000 32.805000 37.586000 33.323000 ;
 RECT 38.274000 32.783000 38.342000 33.277000 ;
 RECT 38.490000 32.783000 38.558000 33.277000 ;
 RECT 39.246000 32.805000 39.314000 33.323000 ;
 RECT 77.262000 15.278000 77.330000 16.132000 ;
 RECT 77.478000 15.278000 77.546000 16.132000 ;
 RECT 77.694000 15.278000 77.762000 16.762000 ;
 RECT 77.910000 15.278000 77.978000 16.762000 ;
 RECT 39.246000 31.117000 39.314000 31.635000 ;
 RECT 40.002000 31.163000 40.070000 31.657000 ;
 RECT 40.218000 31.163000 40.286000 31.657000 ;
 RECT 40.974000 31.117000 41.042000 31.635000 ;
 RECT 39.246000 32.805000 39.314000 33.323000 ;
 RECT 40.002000 32.783000 40.070000 33.277000 ;
 RECT 40.218000 32.783000 40.286000 33.277000 ;
 RECT 40.974000 32.805000 41.042000 33.323000 ;
 RECT 40.974000 31.117000 41.042000 31.635000 ;
 RECT 41.730000 31.163000 41.798000 31.657000 ;
 RECT 41.946000 31.163000 42.014000 31.657000 ;
 RECT 42.702000 31.117000 42.770000 31.635000 ;
 RECT 40.974000 32.805000 41.042000 33.323000 ;
 RECT 41.730000 32.783000 41.798000 33.277000 ;
 RECT 41.946000 32.783000 42.014000 33.277000 ;
 RECT 42.702000 32.805000 42.770000 33.323000 ;
 RECT 42.702000 31.117000 42.770000 31.635000 ;
 RECT 43.458000 31.163000 43.526000 31.657000 ;
 RECT 43.674000 31.163000 43.742000 31.657000 ;
 RECT 44.430000 31.117000 44.498000 31.635000 ;
 RECT 42.702000 32.805000 42.770000 33.323000 ;
 RECT 43.458000 32.783000 43.526000 33.277000 ;
 RECT 43.674000 32.783000 43.742000 33.277000 ;
 RECT 44.430000 32.805000 44.498000 33.323000 ;
 RECT 44.430000 31.117000 44.498000 31.635000 ;
 RECT 45.186000 31.163000 45.254000 31.657000 ;
 RECT 45.402000 31.163000 45.470000 31.657000 ;
 RECT 46.158000 31.117000 46.226000 31.635000 ;
 RECT 44.430000 32.805000 44.498000 33.323000 ;
 RECT 45.186000 32.783000 45.254000 33.277000 ;
 RECT 45.402000 32.783000 45.470000 33.277000 ;
 RECT 46.158000 32.805000 46.226000 33.323000 ;
 RECT 46.158000 31.117000 46.226000 31.635000 ;
 RECT 46.914000 31.163000 46.982000 31.657000 ;
 RECT 47.130000 31.163000 47.198000 31.657000 ;
 RECT 47.886000 31.117000 47.954000 31.635000 ;
 RECT 46.158000 32.805000 46.226000 33.323000 ;
 RECT 46.914000 32.783000 46.982000 33.277000 ;
 RECT 47.130000 32.783000 47.198000 33.277000 ;
 RECT 47.886000 32.805000 47.954000 33.323000 ;
 RECT 77.262000 16.898000 77.330000 17.752000 ;
 RECT 77.478000 16.898000 77.546000 17.752000 ;
 RECT 77.694000 16.898000 77.762000 18.382000 ;
 RECT 77.910000 16.898000 77.978000 18.382000 ;
 RECT 47.886000 31.117000 47.954000 31.635000 ;
 RECT 48.642000 31.163000 48.710000 31.657000 ;
 RECT 48.858000 31.163000 48.926000 31.657000 ;
 RECT 49.614000 31.117000 49.682000 31.635000 ;
 RECT 47.886000 32.805000 47.954000 33.323000 ;
 RECT 48.642000 32.783000 48.710000 33.277000 ;
 RECT 48.858000 32.783000 48.926000 33.277000 ;
 RECT 49.614000 32.805000 49.682000 33.323000 ;
 RECT 49.614000 31.117000 49.682000 31.635000 ;
 RECT 50.370000 31.163000 50.438000 31.657000 ;
 RECT 50.586000 31.163000 50.654000 31.657000 ;
 RECT 51.342000 31.117000 51.410000 31.635000 ;
 RECT 49.614000 32.805000 49.682000 33.323000 ;
 RECT 50.370000 32.783000 50.438000 33.277000 ;
 RECT 50.586000 32.783000 50.654000 33.277000 ;
 RECT 51.342000 32.805000 51.410000 33.323000 ;
 RECT 51.342000 31.117000 51.410000 31.635000 ;
 RECT 52.098000 31.163000 52.166000 31.657000 ;
 RECT 52.314000 31.163000 52.382000 31.657000 ;
 RECT 53.070000 31.117000 53.138000 31.635000 ;
 RECT 51.342000 32.805000 51.410000 33.323000 ;
 RECT 52.098000 32.783000 52.166000 33.277000 ;
 RECT 52.314000 32.783000 52.382000 33.277000 ;
 RECT 53.070000 32.805000 53.138000 33.323000 ;
 RECT 53.070000 31.117000 53.138000 31.635000 ;
 RECT 53.826000 31.163000 53.894000 31.657000 ;
 RECT 54.042000 31.163000 54.110000 31.657000 ;
 RECT 54.798000 31.117000 54.866000 31.635000 ;
 RECT 53.070000 32.805000 53.138000 33.323000 ;
 RECT 53.826000 32.783000 53.894000 33.277000 ;
 RECT 54.042000 32.783000 54.110000 33.277000 ;
 RECT 54.798000 32.805000 54.866000 33.323000 ;
 RECT 54.798000 31.117000 54.866000 31.635000 ;
 RECT 55.554000 31.163000 55.622000 31.657000 ;
 RECT 55.770000 31.163000 55.838000 31.657000 ;
 RECT 56.526000 31.117000 56.594000 31.635000 ;
 RECT 54.798000 32.805000 54.866000 33.323000 ;
 RECT 55.554000 32.783000 55.622000 33.277000 ;
 RECT 55.770000 32.783000 55.838000 33.277000 ;
 RECT 56.526000 32.805000 56.594000 33.323000 ;
 RECT 77.262000 18.518000 77.330000 19.372000 ;
 RECT 77.478000 18.518000 77.546000 19.372000 ;
 RECT 77.694000 18.518000 77.762000 20.002000 ;
 RECT 77.910000 18.518000 77.978000 20.002000 ;
 RECT 83.634000 31.117000 83.702000 31.635000 ;
 RECT 82.878000 31.163000 82.946000 31.657000 ;
 RECT 82.662000 31.163000 82.730000 31.657000 ;
 RECT 81.906000 31.117000 81.974000 31.635000 ;
 RECT 83.634000 32.805000 83.702000 33.323000 ;
 RECT 82.878000 32.783000 82.946000 33.277000 ;
 RECT 82.662000 32.783000 82.730000 33.277000 ;
 RECT 81.906000 32.805000 81.974000 33.323000 ;
 RECT 85.362000 31.117000 85.430000 31.635000 ;
 RECT 84.606000 31.163000 84.674000 31.657000 ;
 RECT 84.390000 31.163000 84.458000 31.657000 ;
 RECT 83.634000 31.117000 83.702000 31.635000 ;
 RECT 85.362000 32.805000 85.430000 33.323000 ;
 RECT 84.606000 32.783000 84.674000 33.277000 ;
 RECT 84.390000 32.783000 84.458000 33.277000 ;
 RECT 83.634000 32.805000 83.702000 33.323000 ;
 RECT 87.090000 31.117000 87.158000 31.635000 ;
 RECT 86.334000 31.163000 86.402000 31.657000 ;
 RECT 86.118000 31.163000 86.186000 31.657000 ;
 RECT 85.362000 31.117000 85.430000 31.635000 ;
 RECT 87.090000 32.805000 87.158000 33.323000 ;
 RECT 86.334000 32.783000 86.402000 33.277000 ;
 RECT 86.118000 32.783000 86.186000 33.277000 ;
 RECT 85.362000 32.805000 85.430000 33.323000 ;
 RECT 88.818000 31.117000 88.886000 31.635000 ;
 RECT 88.062000 31.163000 88.130000 31.657000 ;
 RECT 87.846000 31.163000 87.914000 31.657000 ;
 RECT 87.090000 31.117000 87.158000 31.635000 ;
 RECT 88.818000 32.805000 88.886000 33.323000 ;
 RECT 88.062000 32.783000 88.130000 33.277000 ;
 RECT 87.846000 32.783000 87.914000 33.277000 ;
 RECT 87.090000 32.805000 87.158000 33.323000 ;
 RECT 90.546000 31.117000 90.614000 31.635000 ;
 RECT 89.790000 31.163000 89.858000 31.657000 ;
 RECT 89.574000 31.163000 89.642000 31.657000 ;
 RECT 88.818000 31.117000 88.886000 31.635000 ;
 RECT 90.546000 32.805000 90.614000 33.323000 ;
 RECT 89.790000 32.783000 89.858000 33.277000 ;
 RECT 89.574000 32.783000 89.642000 33.277000 ;
 RECT 88.818000 32.805000 88.886000 33.323000 ;
 RECT 77.262000 20.138000 77.330000 20.992000 ;
 RECT 77.478000 20.138000 77.546000 20.992000 ;
 RECT 77.694000 20.138000 77.762000 21.622000 ;
 RECT 77.910000 20.138000 77.978000 21.622000 ;
 RECT 92.274000 31.117000 92.342000 31.635000 ;
 RECT 91.518000 31.163000 91.586000 31.657000 ;
 RECT 91.302000 31.163000 91.370000 31.657000 ;
 RECT 90.546000 31.117000 90.614000 31.635000 ;
 RECT 92.274000 32.805000 92.342000 33.323000 ;
 RECT 91.518000 32.783000 91.586000 33.277000 ;
 RECT 91.302000 32.783000 91.370000 33.277000 ;
 RECT 90.546000 32.805000 90.614000 33.323000 ;
 RECT 94.002000 31.117000 94.070000 31.635000 ;
 RECT 93.246000 31.163000 93.314000 31.657000 ;
 RECT 93.030000 31.163000 93.098000 31.657000 ;
 RECT 92.274000 31.117000 92.342000 31.635000 ;
 RECT 94.002000 32.805000 94.070000 33.323000 ;
 RECT 93.246000 32.783000 93.314000 33.277000 ;
 RECT 93.030000 32.783000 93.098000 33.277000 ;
 RECT 92.274000 32.805000 92.342000 33.323000 ;
 RECT 95.730000 31.117000 95.798000 31.635000 ;
 RECT 94.974000 31.163000 95.042000 31.657000 ;
 RECT 94.758000 31.163000 94.826000 31.657000 ;
 RECT 94.002000 31.117000 94.070000 31.635000 ;
 RECT 95.730000 32.805000 95.798000 33.323000 ;
 RECT 94.974000 32.783000 95.042000 33.277000 ;
 RECT 94.758000 32.783000 94.826000 33.277000 ;
 RECT 94.002000 32.805000 94.070000 33.323000 ;
 RECT 97.458000 31.117000 97.526000 31.635000 ;
 RECT 96.702000 31.163000 96.770000 31.657000 ;
 RECT 96.486000 31.163000 96.554000 31.657000 ;
 RECT 95.730000 31.117000 95.798000 31.635000 ;
 RECT 97.458000 32.805000 97.526000 33.323000 ;
 RECT 96.702000 32.783000 96.770000 33.277000 ;
 RECT 96.486000 32.783000 96.554000 33.277000 ;
 RECT 95.730000 32.805000 95.798000 33.323000 ;
 RECT 99.186000 31.117000 99.254000 31.635000 ;
 RECT 98.430000 31.163000 98.498000 31.657000 ;
 RECT 98.214000 31.163000 98.282000 31.657000 ;
 RECT 97.458000 31.117000 97.526000 31.635000 ;
 RECT 99.186000 32.805000 99.254000 33.323000 ;
 RECT 98.430000 32.783000 98.498000 33.277000 ;
 RECT 98.214000 32.783000 98.282000 33.277000 ;
 RECT 97.458000 32.805000 97.526000 33.323000 ;
 RECT 77.262000 21.758000 77.330000 22.612000 ;
 RECT 77.478000 21.758000 77.546000 22.612000 ;
 RECT 77.694000 21.758000 77.762000 23.242000 ;
 RECT 77.910000 21.758000 77.978000 23.242000 ;
 RECT 100.914000 31.117000 100.982000 31.635000 ;
 RECT 100.158000 31.163000 100.226000 31.657000 ;
 RECT 99.942000 31.163000 100.010000 31.657000 ;
 RECT 99.186000 31.117000 99.254000 31.635000 ;
 RECT 100.914000 32.805000 100.982000 33.323000 ;
 RECT 100.158000 32.783000 100.226000 33.277000 ;
 RECT 99.942000 32.783000 100.010000 33.277000 ;
 RECT 99.186000 32.805000 99.254000 33.323000 ;
 RECT 102.642000 31.117000 102.710000 31.635000 ;
 RECT 101.886000 31.163000 101.954000 31.657000 ;
 RECT 101.670000 31.163000 101.738000 31.657000 ;
 RECT 100.914000 31.117000 100.982000 31.635000 ;
 RECT 102.642000 32.805000 102.710000 33.323000 ;
 RECT 101.886000 32.783000 101.954000 33.277000 ;
 RECT 101.670000 32.783000 101.738000 33.277000 ;
 RECT 100.914000 32.805000 100.982000 33.323000 ;
 RECT 104.370000 31.117000 104.438000 31.635000 ;
 RECT 103.614000 31.163000 103.682000 31.657000 ;
 RECT 103.398000 31.163000 103.466000 31.657000 ;
 RECT 102.642000 31.117000 102.710000 31.635000 ;
 RECT 104.370000 32.805000 104.438000 33.323000 ;
 RECT 103.614000 32.783000 103.682000 33.277000 ;
 RECT 103.398000 32.783000 103.466000 33.277000 ;
 RECT 102.642000 32.805000 102.710000 33.323000 ;
 RECT 106.098000 31.117000 106.166000 31.635000 ;
 RECT 105.342000 31.163000 105.410000 31.657000 ;
 RECT 105.126000 31.163000 105.194000 31.657000 ;
 RECT 104.370000 31.117000 104.438000 31.635000 ;
 RECT 106.098000 32.805000 106.166000 33.323000 ;
 RECT 105.342000 32.783000 105.410000 33.277000 ;
 RECT 105.126000 32.783000 105.194000 33.277000 ;
 RECT 104.370000 32.805000 104.438000 33.323000 ;
 RECT 107.826000 31.117000 107.894000 31.635000 ;
 RECT 107.070000 31.163000 107.138000 31.657000 ;
 RECT 106.854000 31.163000 106.922000 31.657000 ;
 RECT 106.098000 31.117000 106.166000 31.635000 ;
 RECT 107.826000 32.805000 107.894000 33.323000 ;
 RECT 107.070000 32.783000 107.138000 33.277000 ;
 RECT 106.854000 32.783000 106.922000 33.277000 ;
 RECT 106.098000 32.805000 106.166000 33.323000 ;
 RECT 77.262000 23.378000 77.330000 24.232000 ;
 RECT 77.478000 23.378000 77.546000 24.232000 ;
 RECT 77.694000 23.378000 77.762000 24.862000 ;
 RECT 77.910000 23.378000 77.978000 24.862000 ;
 RECT 109.554000 31.117000 109.622000 31.635000 ;
 RECT 108.798000 31.163000 108.866000 31.657000 ;
 RECT 108.582000 31.163000 108.650000 31.657000 ;
 RECT 107.826000 31.117000 107.894000 31.635000 ;
 RECT 109.554000 32.805000 109.622000 33.323000 ;
 RECT 108.798000 32.783000 108.866000 33.277000 ;
 RECT 108.582000 32.783000 108.650000 33.277000 ;
 RECT 107.826000 32.805000 107.894000 33.323000 ;
 RECT 111.282000 31.117000 111.350000 31.635000 ;
 RECT 110.526000 31.163000 110.594000 31.657000 ;
 RECT 110.310000 31.163000 110.378000 31.657000 ;
 RECT 109.554000 31.117000 109.622000 31.635000 ;
 RECT 111.282000 32.805000 111.350000 33.323000 ;
 RECT 110.526000 32.783000 110.594000 33.277000 ;
 RECT 110.310000 32.783000 110.378000 33.277000 ;
 RECT 109.554000 32.805000 109.622000 33.323000 ;
 RECT 113.010000 31.117000 113.078000 31.635000 ;
 RECT 112.254000 31.163000 112.322000 31.657000 ;
 RECT 112.038000 31.163000 112.106000 31.657000 ;
 RECT 111.282000 31.117000 111.350000 31.635000 ;
 RECT 113.010000 32.805000 113.078000 33.323000 ;
 RECT 112.254000 32.783000 112.322000 33.277000 ;
 RECT 112.038000 32.783000 112.106000 33.277000 ;
 RECT 111.282000 32.805000 111.350000 33.323000 ;
 RECT 114.738000 31.117000 114.806000 31.635000 ;
 RECT 113.982000 31.163000 114.050000 31.657000 ;
 RECT 113.766000 31.163000 113.834000 31.657000 ;
 RECT 113.010000 31.117000 113.078000 31.635000 ;
 RECT 114.738000 32.805000 114.806000 33.323000 ;
 RECT 113.982000 32.783000 114.050000 33.277000 ;
 RECT 113.766000 32.783000 113.834000 33.277000 ;
 RECT 113.010000 32.805000 113.078000 33.323000 ;
 RECT 116.466000 31.117000 116.534000 31.635000 ;
 RECT 115.710000 31.163000 115.778000 31.657000 ;
 RECT 115.494000 31.163000 115.562000 31.657000 ;
 RECT 114.738000 31.117000 114.806000 31.635000 ;
 RECT 116.466000 32.805000 116.534000 33.323000 ;
 RECT 115.710000 32.783000 115.778000 33.277000 ;
 RECT 115.494000 32.783000 115.562000 33.277000 ;
 RECT 114.738000 32.805000 114.806000 33.323000 ;
 RECT 77.262000 24.998000 77.330000 25.852000 ;
 RECT 77.478000 24.998000 77.546000 25.852000 ;
 RECT 77.694000 24.998000 77.762000 26.482000 ;
 RECT 77.910000 24.998000 77.978000 26.482000 ;
 RECT 118.194000 31.117000 118.262000 31.635000 ;
 RECT 117.438000 31.163000 117.506000 31.657000 ;
 RECT 117.222000 31.163000 117.290000 31.657000 ;
 RECT 116.466000 31.117000 116.534000 31.635000 ;
 RECT 118.194000 32.805000 118.262000 33.323000 ;
 RECT 117.438000 32.783000 117.506000 33.277000 ;
 RECT 117.222000 32.783000 117.290000 33.277000 ;
 RECT 116.466000 32.805000 116.534000 33.323000 ;
 RECT 119.922000 31.117000 119.990000 31.635000 ;
 RECT 119.166000 31.163000 119.234000 31.657000 ;
 RECT 118.950000 31.163000 119.018000 31.657000 ;
 RECT 118.194000 31.117000 118.262000 31.635000 ;
 RECT 119.922000 32.805000 119.990000 33.323000 ;
 RECT 119.166000 32.783000 119.234000 33.277000 ;
 RECT 118.950000 32.783000 119.018000 33.277000 ;
 RECT 118.194000 32.805000 118.262000 33.323000 ;
 RECT 121.650000 31.117000 121.718000 31.635000 ;
 RECT 120.894000 31.163000 120.962000 31.657000 ;
 RECT 120.678000 31.163000 120.746000 31.657000 ;
 RECT 119.922000 31.117000 119.990000 31.635000 ;
 RECT 121.650000 32.805000 121.718000 33.323000 ;
 RECT 120.894000 32.783000 120.962000 33.277000 ;
 RECT 120.678000 32.783000 120.746000 33.277000 ;
 RECT 119.922000 32.805000 119.990000 33.323000 ;
 RECT 123.378000 31.117000 123.446000 31.635000 ;
 RECT 122.622000 31.163000 122.690000 31.657000 ;
 RECT 122.406000 31.163000 122.474000 31.657000 ;
 RECT 121.650000 31.117000 121.718000 31.635000 ;
 RECT 123.378000 32.805000 123.446000 33.323000 ;
 RECT 122.622000 32.783000 122.690000 33.277000 ;
 RECT 122.406000 32.783000 122.474000 33.277000 ;
 RECT 121.650000 32.805000 121.718000 33.323000 ;
 RECT 125.106000 31.117000 125.174000 31.635000 ;
 RECT 124.350000 31.163000 124.418000 31.657000 ;
 RECT 124.134000 31.163000 124.202000 31.657000 ;
 RECT 123.378000 31.117000 123.446000 31.635000 ;
 RECT 125.106000 32.805000 125.174000 33.323000 ;
 RECT 124.350000 32.783000 124.418000 33.277000 ;
 RECT 124.134000 32.783000 124.202000 33.277000 ;
 RECT 123.378000 32.805000 123.446000 33.323000 ;
 RECT 77.262000 39.218000 77.330000 40.072000 ;
 RECT 77.478000 39.218000 77.546000 40.072000 ;
 RECT 77.694000 39.218000 77.762000 40.702000 ;
 RECT 77.910000 39.218000 77.978000 40.702000 ;
 RECT 126.834000 31.117000 126.902000 31.635000 ;
 RECT 126.078000 31.163000 126.146000 31.657000 ;
 RECT 125.862000 31.163000 125.930000 31.657000 ;
 RECT 125.106000 31.117000 125.174000 31.635000 ;
 RECT 126.834000 32.805000 126.902000 33.323000 ;
 RECT 126.078000 32.783000 126.146000 33.277000 ;
 RECT 125.862000 32.783000 125.930000 33.277000 ;
 RECT 125.106000 32.805000 125.174000 33.323000 ;
 RECT 128.562000 31.117000 128.630000 31.635000 ;
 RECT 127.806000 31.163000 127.874000 31.657000 ;
 RECT 127.590000 31.163000 127.658000 31.657000 ;
 RECT 126.834000 31.117000 126.902000 31.635000 ;
 RECT 128.562000 32.805000 128.630000 33.323000 ;
 RECT 127.806000 32.783000 127.874000 33.277000 ;
 RECT 127.590000 32.783000 127.658000 33.277000 ;
 RECT 126.834000 32.805000 126.902000 33.323000 ;
 RECT 130.290000 31.117000 130.358000 31.635000 ;
 RECT 129.534000 31.163000 129.602000 31.657000 ;
 RECT 129.318000 31.163000 129.386000 31.657000 ;
 RECT 128.562000 31.117000 128.630000 31.635000 ;
 RECT 130.290000 32.805000 130.358000 33.323000 ;
 RECT 129.534000 32.783000 129.602000 33.277000 ;
 RECT 129.318000 32.783000 129.386000 33.277000 ;
 RECT 128.562000 32.805000 128.630000 33.323000 ;
 RECT 132.018000 31.117000 132.086000 31.635000 ;
 RECT 131.262000 31.163000 131.330000 31.657000 ;
 RECT 131.046000 31.163000 131.114000 31.657000 ;
 RECT 130.290000 31.117000 130.358000 31.635000 ;
 RECT 132.018000 32.805000 132.086000 33.323000 ;
 RECT 131.262000 32.783000 131.330000 33.277000 ;
 RECT 131.046000 32.783000 131.114000 33.277000 ;
 RECT 130.290000 32.805000 130.358000 33.323000 ;
 RECT 133.746000 31.117000 133.814000 31.635000 ;
 RECT 132.990000 31.163000 133.058000 31.657000 ;
 RECT 132.774000 31.163000 132.842000 31.657000 ;
 RECT 132.018000 31.117000 132.086000 31.635000 ;
 RECT 133.746000 32.805000 133.814000 33.323000 ;
 RECT 132.990000 32.783000 133.058000 33.277000 ;
 RECT 132.774000 32.783000 132.842000 33.277000 ;
 RECT 132.018000 32.805000 132.086000 33.323000 ;
 RECT 77.262000 40.838000 77.330000 41.692000 ;
 RECT 77.478000 40.838000 77.546000 41.692000 ;
 RECT 77.694000 40.838000 77.762000 42.322000 ;
 RECT 77.910000 40.838000 77.978000 42.322000 ;
 RECT 135.474000 31.117000 135.542000 31.635000 ;
 RECT 134.718000 31.163000 134.786000 31.657000 ;
 RECT 134.502000 31.163000 134.570000 31.657000 ;
 RECT 133.746000 31.117000 133.814000 31.635000 ;
 RECT 135.474000 32.805000 135.542000 33.323000 ;
 RECT 134.718000 32.783000 134.786000 33.277000 ;
 RECT 134.502000 32.783000 134.570000 33.277000 ;
 RECT 133.746000 32.805000 133.814000 33.323000 ;
 RECT 137.202000 31.117000 137.270000 31.635000 ;
 RECT 136.446000 31.163000 136.514000 31.657000 ;
 RECT 136.230000 31.163000 136.298000 31.657000 ;
 RECT 135.474000 31.117000 135.542000 31.635000 ;
 RECT 137.202000 32.805000 137.270000 33.323000 ;
 RECT 136.446000 32.783000 136.514000 33.277000 ;
 RECT 136.230000 32.783000 136.298000 33.277000 ;
 RECT 135.474000 32.805000 135.542000 33.323000 ;
 RECT 59.658000 27.878000 59.726000 29.092000 ;
 RECT 59.874000 27.878000 59.942000 29.092000 ;
 RECT 60.090000 28.360000 60.158000 29.092000 ;
 RECT 60.306000 28.328000 60.374000 29.092000 ;
 RECT 60.522000 28.328000 60.590000 29.092000 ;
 RECT 59.658000 29.138000 59.726000 30.352000 ;
 RECT 59.874000 29.138000 59.942000 30.352000 ;
 RECT 60.090000 29.620000 60.158000 30.352000 ;
 RECT 60.306000 29.588000 60.374000 30.352000 ;
 RECT 60.522000 29.588000 60.590000 30.352000 ;
 RECT 59.658000 30.398000 59.726000 31.612000 ;
 RECT 59.874000 30.398000 59.942000 31.612000 ;
 RECT 60.090000 30.880000 60.158000 31.612000 ;
 RECT 60.306000 30.848000 60.374000 31.612000 ;
 RECT 60.522000 30.848000 60.590000 31.612000 ;
 RECT 59.658000 31.658000 59.726000 32.872000 ;
 RECT 59.874000 31.658000 59.942000 32.872000 ;
 RECT 60.090000 32.140000 60.158000 32.872000 ;
 RECT 60.306000 32.108000 60.374000 32.872000 ;
 RECT 60.522000 32.108000 60.590000 32.872000 ;
 RECT 59.658000 32.918000 59.726000 34.132000 ;
 RECT 59.874000 32.918000 59.942000 34.132000 ;
 RECT 60.090000 33.400000 60.158000 34.132000 ;
 RECT 60.306000 33.368000 60.374000 34.132000 ;
 RECT 60.522000 33.368000 60.590000 34.132000 ;
 RECT 59.658000 34.178000 59.726000 35.392000 ;
 RECT 59.874000 34.178000 59.942000 35.392000 ;
 RECT 60.090000 34.660000 60.158000 35.392000 ;
 RECT 60.306000 34.628000 60.374000 35.392000 ;
 RECT 60.522000 34.628000 60.590000 35.392000 ;
 RECT 77.262000 0.698000 77.330000 1.552000 ;
 RECT 77.478000 0.698000 77.546000 1.552000 ;
 RECT 77.694000 0.698000 77.762000 2.182000 ;
 RECT 77.910000 0.698000 77.978000 2.182000 ;
 RECT 77.262000 42.458000 77.330000 43.312000 ;
 RECT 77.478000 42.458000 77.546000 43.312000 ;
 RECT 77.694000 42.458000 77.762000 43.942000 ;
 RECT 77.910000 42.458000 77.978000 43.942000 ;
 RECT 59.658000 35.438000 59.726000 36.652000 ;
 RECT 59.874000 35.438000 59.942000 36.652000 ;
 RECT 60.090000 35.920000 60.158000 36.652000 ;
 RECT 60.306000 35.888000 60.374000 36.652000 ;
 RECT 60.522000 35.888000 60.590000 36.652000 ;
 RECT 59.658000 36.698000 59.726000 37.912000 ;
 RECT 59.874000 36.698000 59.942000 37.912000 ;
 RECT 60.090000 37.180000 60.158000 37.912000 ;
 RECT 60.306000 37.148000 60.374000 37.912000 ;
 RECT 60.522000 37.148000 60.590000 37.912000 ;
 RECT 78.774000 27.788000 78.842000 29.002000 ;
 RECT 78.558000 27.788000 78.626000 29.002000 ;
 RECT 78.342000 27.788000 78.410000 28.520000 ;
 RECT 78.126000 27.788000 78.194000 28.552000 ;
 RECT 77.910000 27.788000 77.978000 28.552000 ;
 RECT 78.774000 29.048000 78.842000 30.262000 ;
 RECT 78.558000 29.048000 78.626000 30.262000 ;
 RECT 78.342000 29.048000 78.410000 29.780000 ;
 RECT 78.126000 29.048000 78.194000 29.812000 ;
 RECT 77.910000 29.048000 77.978000 29.812000 ;
 RECT 78.774000 30.308000 78.842000 31.522000 ;
 RECT 78.558000 30.308000 78.626000 31.522000 ;
 RECT 78.342000 30.308000 78.410000 31.040000 ;
 RECT 78.126000 30.308000 78.194000 31.072000 ;
 RECT 77.910000 30.308000 77.978000 31.072000 ;
 RECT 78.774000 31.568000 78.842000 32.782000 ;
 RECT 78.558000 31.568000 78.626000 32.782000 ;
 RECT 78.342000 31.568000 78.410000 32.300000 ;
 RECT 78.126000 31.568000 78.194000 32.332000 ;
 RECT 77.910000 31.568000 77.978000 32.332000 ;
 RECT 78.774000 32.828000 78.842000 34.042000 ;
 RECT 78.558000 32.828000 78.626000 34.042000 ;
 RECT 78.342000 32.828000 78.410000 33.560000 ;
 RECT 78.126000 32.828000 78.194000 33.592000 ;
 RECT 77.910000 32.828000 77.978000 33.592000 ;
 RECT 78.774000 34.088000 78.842000 35.302000 ;
 RECT 78.558000 34.088000 78.626000 35.302000 ;
 RECT 78.342000 34.088000 78.410000 34.820000 ;
 RECT 78.126000 34.088000 78.194000 34.852000 ;
 RECT 77.910000 34.088000 77.978000 34.852000 ;
 RECT 78.774000 35.348000 78.842000 36.562000 ;
 RECT 78.558000 35.348000 78.626000 36.562000 ;
 RECT 78.342000 35.348000 78.410000 36.080000 ;
 RECT 78.126000 35.348000 78.194000 36.112000 ;
 RECT 77.910000 35.348000 77.978000 36.112000 ;
 RECT 78.774000 36.608000 78.842000 37.822000 ;
 RECT 78.558000 36.608000 78.626000 37.822000 ;
 RECT 78.342000 36.608000 78.410000 37.340000 ;
 RECT 78.126000 36.608000 78.194000 37.372000 ;
 RECT 77.910000 36.608000 77.978000 37.372000 ;
 RECT 77.262000 44.078000 77.330000 44.932000 ;
 RECT 77.478000 44.078000 77.546000 44.932000 ;
 RECT 77.694000 44.078000 77.762000 45.562000 ;
 RECT 77.910000 44.078000 77.978000 45.562000 ;
 RECT 77.262000 45.698000 77.330000 46.552000 ;
 RECT 77.478000 45.698000 77.546000 46.552000 ;
 RECT 77.694000 45.698000 77.762000 47.182000 ;
 RECT 77.910000 45.698000 77.978000 47.182000 ;
 RECT 77.262000 47.318000 77.330000 48.172000 ;
 RECT 77.478000 47.318000 77.546000 48.172000 ;
 RECT 77.694000 47.318000 77.762000 48.802000 ;
 RECT 77.910000 47.318000 77.978000 48.802000 ;
 RECT 77.262000 48.938000 77.330000 49.792000 ;
 RECT 77.478000 48.938000 77.546000 49.792000 ;
 RECT 77.694000 48.938000 77.762000 50.422000 ;
 RECT 77.910000 48.938000 77.978000 50.422000 ;
 RECT 77.262000 50.558000 77.330000 51.412000 ;
 RECT 77.478000 50.558000 77.546000 51.412000 ;
 RECT 77.694000 50.558000 77.762000 52.042000 ;
 RECT 77.910000 50.558000 77.978000 52.042000 ;
 RECT 77.262000 52.178000 77.330000 53.032000 ;
 RECT 77.478000 52.178000 77.546000 53.032000 ;
 RECT 77.694000 52.178000 77.762000 53.662000 ;
 RECT 77.910000 52.178000 77.978000 53.662000 ;
 RECT 77.262000 53.798000 77.330000 54.652000 ;
 RECT 77.478000 53.798000 77.546000 54.652000 ;
 RECT 77.694000 53.798000 77.762000 55.282000 ;
 RECT 77.910000 53.798000 77.978000 55.282000 ;
 RECT 77.262000 55.418000 77.330000 56.272000 ;
 RECT 77.478000 55.418000 77.546000 56.272000 ;
 RECT 77.694000 55.418000 77.762000 56.902000 ;
 RECT 77.910000 55.418000 77.978000 56.902000 ;
 RECT 77.262000 57.038000 77.330000 57.892000 ;
 RECT 77.478000 57.038000 77.546000 57.892000 ;
 RECT 77.694000 57.038000 77.762000 58.522000 ;
 RECT 77.910000 57.038000 77.978000 58.522000 ;
 RECT 77.262000 2.318000 77.330000 3.172000 ;
 RECT 77.478000 2.318000 77.546000 3.172000 ;
 RECT 77.694000 2.318000 77.762000 3.802000 ;
 RECT 77.910000 2.318000 77.978000 3.802000 ;
 RECT 77.262000 58.658000 77.330000 59.512000 ;
 RECT 77.478000 58.658000 77.546000 59.512000 ;
 RECT 77.694000 58.658000 77.762000 60.142000 ;
 RECT 77.910000 58.658000 77.978000 60.142000 ;
 RECT 77.262000 60.278000 77.330000 61.132000 ;
 RECT 77.478000 60.278000 77.546000 61.132000 ;
 RECT 77.694000 60.278000 77.762000 61.762000 ;
 RECT 77.910000 60.278000 77.978000 61.762000 ;
 RECT 77.262000 61.898000 77.330000 62.752000 ;
 RECT 77.478000 61.898000 77.546000 62.752000 ;
 RECT 77.694000 61.898000 77.762000 63.382000 ;
 RECT 77.910000 61.898000 77.978000 63.382000 ;
 RECT 77.262000 63.518000 77.330000 64.372000 ;
 RECT 77.478000 63.518000 77.546000 64.372000 ;
 RECT 77.694000 63.518000 77.762000 65.002000 ;
 RECT 77.910000 63.518000 77.978000 65.002000 ;
 RECT 60.522000 0.698000 60.590000 2.182000 ;
 RECT 60.738000 0.698000 60.806000 2.182000 ;
 RECT 60.954000 1.328000 61.022000 2.182000 ;
 RECT 61.170000 1.328000 61.238000 2.182000 ;
 RECT 60.522000 2.318000 60.590000 3.802000 ;
 RECT 60.738000 2.318000 60.806000 3.802000 ;
 RECT 60.954000 2.948000 61.022000 3.802000 ;
 RECT 61.170000 2.948000 61.238000 3.802000 ;
 RECT 60.522000 3.938000 60.590000 5.422000 ;
 RECT 60.738000 3.938000 60.806000 5.422000 ;
 RECT 60.954000 4.568000 61.022000 5.422000 ;
 RECT 61.170000 4.568000 61.238000 5.422000 ;
 RECT 60.522000 5.558000 60.590000 7.042000 ;
 RECT 60.738000 5.558000 60.806000 7.042000 ;
 RECT 60.954000 6.188000 61.022000 7.042000 ;
 RECT 61.170000 6.188000 61.238000 7.042000 ;
 RECT 60.522000 7.178000 60.590000 8.662000 ;
 RECT 60.738000 7.178000 60.806000 8.662000 ;
 RECT 60.954000 7.808000 61.022000 8.662000 ;
 RECT 61.170000 7.808000 61.238000 8.662000 ;
 RECT 60.522000 8.798000 60.590000 10.282000 ;
 RECT 60.738000 8.798000 60.806000 10.282000 ;
 RECT 60.954000 9.428000 61.022000 10.282000 ;
 RECT 61.170000 9.428000 61.238000 10.282000 ;
 RECT 77.262000 3.938000 77.330000 4.792000 ;
 RECT 77.478000 3.938000 77.546000 4.792000 ;
 RECT 77.694000 3.938000 77.762000 5.422000 ;
 RECT 77.910000 3.938000 77.978000 5.422000 ;
 RECT 60.522000 10.418000 60.590000 11.902000 ;
 RECT 60.738000 10.418000 60.806000 11.902000 ;
 RECT 60.954000 11.048000 61.022000 11.902000 ;
 RECT 61.170000 11.048000 61.238000 11.902000 ;
 RECT 60.522000 12.038000 60.590000 13.522000 ;
 RECT 60.738000 12.038000 60.806000 13.522000 ;
 RECT 60.954000 12.668000 61.022000 13.522000 ;
 RECT 61.170000 12.668000 61.238000 13.522000 ;
 RECT 60.522000 13.658000 60.590000 15.142000 ;
 RECT 60.738000 13.658000 60.806000 15.142000 ;
 RECT 60.954000 14.288000 61.022000 15.142000 ;
 RECT 61.170000 14.288000 61.238000 15.142000 ;
 RECT 60.522000 15.278000 60.590000 16.762000 ;
 RECT 60.738000 15.278000 60.806000 16.762000 ;
 RECT 60.954000 15.908000 61.022000 16.762000 ;
 RECT 61.170000 15.908000 61.238000 16.762000 ;
 RECT 60.522000 16.898000 60.590000 18.382000 ;
 RECT 60.738000 16.898000 60.806000 18.382000 ;
 RECT 60.954000 17.528000 61.022000 18.382000 ;
 RECT 61.170000 17.528000 61.238000 18.382000 ;
 RECT 60.522000 18.518000 60.590000 20.002000 ;
 RECT 60.738000 18.518000 60.806000 20.002000 ;
 RECT 60.954000 19.148000 61.022000 20.002000 ;
 RECT 61.170000 19.148000 61.238000 20.002000 ;
 RECT 60.522000 20.138000 60.590000 21.622000 ;
 RECT 60.738000 20.138000 60.806000 21.622000 ;
 RECT 60.954000 20.768000 61.022000 21.622000 ;
 RECT 61.170000 20.768000 61.238000 21.622000 ;
 RECT 60.522000 21.758000 60.590000 23.242000 ;
 RECT 60.738000 21.758000 60.806000 23.242000 ;
 RECT 60.954000 22.388000 61.022000 23.242000 ;
 RECT 61.170000 22.388000 61.238000 23.242000 ;
 RECT 60.522000 23.378000 60.590000 24.862000 ;
 RECT 60.738000 23.378000 60.806000 24.862000 ;
 RECT 60.954000 24.008000 61.022000 24.862000 ;
 RECT 61.170000 24.008000 61.238000 24.862000 ;
 RECT 60.522000 24.998000 60.590000 26.482000 ;
 RECT 60.738000 24.998000 60.806000 26.482000 ;
 RECT 60.954000 25.628000 61.022000 26.482000 ;
 RECT 61.170000 25.628000 61.238000 26.482000 ;
 RECT 77.262000 5.558000 77.330000 6.412000 ;
 RECT 77.478000 5.558000 77.546000 6.412000 ;
 RECT 77.694000 5.558000 77.762000 7.042000 ;
 RECT 77.910000 5.558000 77.978000 7.042000 ;
 RECT 60.522000 39.218000 60.590000 40.702000 ;
 RECT 60.738000 39.218000 60.806000 40.702000 ;
 RECT 60.954000 39.848000 61.022000 40.702000 ;
 RECT 61.170000 39.848000 61.238000 40.702000 ;
 RECT 60.522000 40.838000 60.590000 42.322000 ;
 RECT 60.738000 40.838000 60.806000 42.322000 ;
 RECT 60.954000 41.468000 61.022000 42.322000 ;
 RECT 61.170000 41.468000 61.238000 42.322000 ;
 RECT 60.522000 42.458000 60.590000 43.942000 ;
 RECT 60.738000 42.458000 60.806000 43.942000 ;
 RECT 60.954000 43.088000 61.022000 43.942000 ;
 RECT 61.170000 43.088000 61.238000 43.942000 ;
 RECT 60.522000 44.078000 60.590000 45.562000 ;
 RECT 60.738000 44.078000 60.806000 45.562000 ;
 RECT 60.954000 44.708000 61.022000 45.562000 ;
 RECT 61.170000 44.708000 61.238000 45.562000 ;
 RECT 60.522000 45.698000 60.590000 47.182000 ;
 RECT 60.738000 45.698000 60.806000 47.182000 ;
 RECT 60.954000 46.328000 61.022000 47.182000 ;
 RECT 61.170000 46.328000 61.238000 47.182000 ;
 RECT 60.522000 47.318000 60.590000 48.802000 ;
 RECT 60.738000 47.318000 60.806000 48.802000 ;
 RECT 60.954000 47.948000 61.022000 48.802000 ;
 RECT 61.170000 47.948000 61.238000 48.802000 ;
 RECT 60.522000 48.938000 60.590000 50.422000 ;
 RECT 60.738000 48.938000 60.806000 50.422000 ;
 RECT 60.954000 49.568000 61.022000 50.422000 ;
 RECT 61.170000 49.568000 61.238000 50.422000 ;
 RECT 60.522000 50.558000 60.590000 52.042000 ;
 RECT 60.738000 50.558000 60.806000 52.042000 ;
 RECT 60.954000 51.188000 61.022000 52.042000 ;
 RECT 61.170000 51.188000 61.238000 52.042000 ;
 RECT 60.522000 52.178000 60.590000 53.662000 ;
 RECT 60.738000 52.178000 60.806000 53.662000 ;
 RECT 60.954000 52.808000 61.022000 53.662000 ;
 RECT 61.170000 52.808000 61.238000 53.662000 ;
 RECT 60.522000 53.798000 60.590000 55.282000 ;
 RECT 60.738000 53.798000 60.806000 55.282000 ;
 RECT 60.954000 54.428000 61.022000 55.282000 ;
 RECT 61.170000 54.428000 61.238000 55.282000 ;
 RECT 77.262000 7.178000 77.330000 8.032000 ;
 RECT 77.478000 7.178000 77.546000 8.032000 ;
 RECT 77.694000 7.178000 77.762000 8.662000 ;
 RECT 77.910000 7.178000 77.978000 8.662000 ;
 RECT 60.522000 55.418000 60.590000 56.902000 ;
 RECT 60.738000 55.418000 60.806000 56.902000 ;
 RECT 60.954000 56.048000 61.022000 56.902000 ;
 RECT 61.170000 56.048000 61.238000 56.902000 ;
 RECT 60.522000 57.038000 60.590000 58.522000 ;
 RECT 60.738000 57.038000 60.806000 58.522000 ;
 RECT 60.954000 57.668000 61.022000 58.522000 ;
 RECT 61.170000 57.668000 61.238000 58.522000 ;
 RECT 60.522000 58.658000 60.590000 60.142000 ;
 RECT 60.738000 58.658000 60.806000 60.142000 ;
 RECT 60.954000 59.288000 61.022000 60.142000 ;
 RECT 61.170000 59.288000 61.238000 60.142000 ;
 RECT 60.522000 60.278000 60.590000 61.762000 ;
 RECT 60.738000 60.278000 60.806000 61.762000 ;
 RECT 60.954000 60.908000 61.022000 61.762000 ;
 RECT 61.170000 60.908000 61.238000 61.762000 ;
 RECT 60.522000 61.898000 60.590000 63.382000 ;
 RECT 60.738000 61.898000 60.806000 63.382000 ;
 RECT 60.954000 62.528000 61.022000 63.382000 ;
 RECT 61.170000 62.528000 61.238000 63.382000 ;
 RECT 60.522000 63.518000 60.590000 65.002000 ;
 RECT 60.738000 63.518000 60.806000 65.002000 ;
 RECT 60.954000 64.148000 61.022000 65.002000 ;
 RECT 61.170000 64.148000 61.238000 65.002000 ;
 RECT 1.230000 31.117000 1.298000 31.635000 ;
 RECT 1.986000 31.163000 2.054000 31.657000 ;
 RECT 2.202000 31.163000 2.270000 31.657000 ;
 RECT 2.958000 31.117000 3.026000 31.635000 ;
 RECT 1.230000 32.805000 1.298000 33.323000 ;
 RECT 1.986000 32.783000 2.054000 33.277000 ;
 RECT 2.202000 32.783000 2.270000 33.277000 ;
 RECT 2.958000 32.805000 3.026000 33.323000 ;
 RECT 2.958000 31.117000 3.026000 31.635000 ;
 RECT 3.714000 31.163000 3.782000 31.657000 ;
 RECT 3.930000 31.163000 3.998000 31.657000 ;
 RECT 4.686000 31.117000 4.754000 31.635000 ;
 RECT 2.958000 32.805000 3.026000 33.323000 ;
 RECT 3.714000 32.783000 3.782000 33.277000 ;
 RECT 3.930000 32.783000 3.998000 33.277000 ;
 RECT 4.686000 32.805000 4.754000 33.323000 ;
 RECT 77.262000 8.798000 77.330000 9.652000 ;
 RECT 77.478000 8.798000 77.546000 9.652000 ;
 RECT 77.694000 8.798000 77.762000 10.282000 ;
 RECT 77.910000 8.798000 77.978000 10.282000 ;
 RECT 4.686000 31.117000 4.754000 31.635000 ;
 RECT 5.442000 31.163000 5.510000 31.657000 ;
 RECT 5.658000 31.163000 5.726000 31.657000 ;
 RECT 6.414000 31.117000 6.482000 31.635000 ;
 RECT 4.686000 32.805000 4.754000 33.323000 ;
 RECT 5.442000 32.783000 5.510000 33.277000 ;
 RECT 5.658000 32.783000 5.726000 33.277000 ;
 RECT 6.414000 32.805000 6.482000 33.323000 ;
 RECT 6.414000 31.117000 6.482000 31.635000 ;
 RECT 7.170000 31.163000 7.238000 31.657000 ;
 RECT 7.386000 31.163000 7.454000 31.657000 ;
 RECT 8.142000 31.117000 8.210000 31.635000 ;
 RECT 6.414000 32.805000 6.482000 33.323000 ;
 RECT 7.170000 32.783000 7.238000 33.277000 ;
 RECT 7.386000 32.783000 7.454000 33.277000 ;
 RECT 8.142000 32.805000 8.210000 33.323000 ;
 RECT 8.142000 31.117000 8.210000 31.635000 ;
 RECT 8.898000 31.163000 8.966000 31.657000 ;
 RECT 9.114000 31.163000 9.182000 31.657000 ;
 RECT 9.870000 31.117000 9.938000 31.635000 ;
 RECT 8.142000 32.805000 8.210000 33.323000 ;
 RECT 8.898000 32.783000 8.966000 33.277000 ;
 RECT 9.114000 32.783000 9.182000 33.277000 ;
 RECT 9.870000 32.805000 9.938000 33.323000 ;
 RECT 9.870000 31.117000 9.938000 31.635000 ;
 RECT 10.626000 31.163000 10.694000 31.657000 ;
 RECT 10.842000 31.163000 10.910000 31.657000 ;
 RECT 11.598000 31.117000 11.666000 31.635000 ;
 RECT 9.870000 32.805000 9.938000 33.323000 ;
 RECT 10.626000 32.783000 10.694000 33.277000 ;
 RECT 10.842000 32.783000 10.910000 33.277000 ;
 RECT 11.598000 32.805000 11.666000 33.323000 ;
 RECT 11.598000 31.117000 11.666000 31.635000 ;
 RECT 12.354000 31.163000 12.422000 31.657000 ;
 RECT 12.570000 31.163000 12.638000 31.657000 ;
 RECT 13.326000 31.117000 13.394000 31.635000 ;
 RECT 11.598000 32.805000 11.666000 33.323000 ;
 RECT 12.354000 32.783000 12.422000 33.277000 ;
 RECT 12.570000 32.783000 12.638000 33.277000 ;
 RECT 13.326000 32.805000 13.394000 33.323000 ;
 RECT 77.262000 10.418000 77.330000 11.272000 ;
 RECT 77.478000 10.418000 77.546000 11.272000 ;
 RECT 77.694000 10.418000 77.762000 11.902000 ;
 RECT 77.910000 10.418000 77.978000 11.902000 ;
 RECT 13.326000 31.117000 13.394000 31.635000 ;
 RECT 14.082000 31.163000 14.150000 31.657000 ;
 RECT 14.298000 31.163000 14.366000 31.657000 ;
 RECT 15.054000 31.117000 15.122000 31.635000 ;
 RECT 13.326000 32.805000 13.394000 33.323000 ;
 RECT 14.082000 32.783000 14.150000 33.277000 ;
 RECT 14.298000 32.783000 14.366000 33.277000 ;
 RECT 15.054000 32.805000 15.122000 33.323000 ;
 RECT 15.054000 31.117000 15.122000 31.635000 ;
 RECT 15.810000 31.163000 15.878000 31.657000 ;
 RECT 16.026000 31.163000 16.094000 31.657000 ;
 RECT 16.782000 31.117000 16.850000 31.635000 ;
 RECT 15.054000 32.805000 15.122000 33.323000 ;
 RECT 15.810000 32.783000 15.878000 33.277000 ;
 RECT 16.026000 32.783000 16.094000 33.277000 ;
 RECT 16.782000 32.805000 16.850000 33.323000 ;
 RECT 16.782000 31.117000 16.850000 31.635000 ;
 RECT 17.538000 31.163000 17.606000 31.657000 ;
 RECT 17.754000 31.163000 17.822000 31.657000 ;
 RECT 18.510000 31.117000 18.578000 31.635000 ;
 RECT 16.782000 32.805000 16.850000 33.323000 ;
 RECT 17.538000 32.783000 17.606000 33.277000 ;
 RECT 17.754000 32.783000 17.822000 33.277000 ;
 RECT 18.510000 32.805000 18.578000 33.323000 ;
 RECT 18.510000 31.117000 18.578000 31.635000 ;
 RECT 19.266000 31.163000 19.334000 31.657000 ;
 RECT 19.482000 31.163000 19.550000 31.657000 ;
 RECT 20.238000 31.117000 20.306000 31.635000 ;
 RECT 18.510000 32.805000 18.578000 33.323000 ;
 RECT 19.266000 32.783000 19.334000 33.277000 ;
 RECT 19.482000 32.783000 19.550000 33.277000 ;
 RECT 20.238000 32.805000 20.306000 33.323000 ;
 RECT 20.238000 31.117000 20.306000 31.635000 ;
 RECT 20.994000 31.163000 21.062000 31.657000 ;
 RECT 21.210000 31.163000 21.278000 31.657000 ;
 RECT 21.966000 31.117000 22.034000 31.635000 ;
 RECT 20.238000 32.805000 20.306000 33.323000 ;
 RECT 20.994000 32.783000 21.062000 33.277000 ;
 RECT 21.210000 32.783000 21.278000 33.277000 ;
 RECT 21.966000 32.805000 22.034000 33.323000 ;
 RECT 77.262000 12.038000 77.330000 12.892000 ;
 RECT 77.478000 12.038000 77.546000 12.892000 ;
 RECT 77.694000 12.038000 77.762000 13.522000 ;
 RECT 77.910000 12.038000 77.978000 13.522000 ;
 RECT 21.966000 31.117000 22.034000 31.635000 ;
 RECT 22.722000 31.163000 22.790000 31.657000 ;
 RECT 22.938000 31.163000 23.006000 31.657000 ;
 RECT 23.694000 31.117000 23.762000 31.635000 ;
 RECT 21.966000 32.805000 22.034000 33.323000 ;
 RECT 22.722000 32.783000 22.790000 33.277000 ;
 RECT 22.938000 32.783000 23.006000 33.277000 ;
 RECT 23.694000 32.805000 23.762000 33.323000 ;
 RECT 23.694000 31.117000 23.762000 31.635000 ;
 RECT 24.450000 31.163000 24.518000 31.657000 ;
 RECT 24.666000 31.163000 24.734000 31.657000 ;
 RECT 25.422000 31.117000 25.490000 31.635000 ;
 RECT 23.694000 32.805000 23.762000 33.323000 ;
 RECT 24.450000 32.783000 24.518000 33.277000 ;
 RECT 24.666000 32.783000 24.734000 33.277000 ;
 RECT 25.422000 32.805000 25.490000 33.323000 ;
 RECT 25.422000 31.117000 25.490000 31.635000 ;
 RECT 26.178000 31.163000 26.246000 31.657000 ;
 RECT 26.394000 31.163000 26.462000 31.657000 ;
 RECT 27.150000 31.117000 27.218000 31.635000 ;
 RECT 25.422000 32.805000 25.490000 33.323000 ;
 RECT 26.178000 32.783000 26.246000 33.277000 ;
 RECT 26.394000 32.783000 26.462000 33.277000 ;
 RECT 27.150000 32.805000 27.218000 33.323000 ;
 RECT 27.150000 31.117000 27.218000 31.635000 ;
 RECT 27.906000 31.163000 27.974000 31.657000 ;
 RECT 28.122000 31.163000 28.190000 31.657000 ;
 RECT 28.878000 31.117000 28.946000 31.635000 ;
 RECT 27.150000 32.805000 27.218000 33.323000 ;
 RECT 27.906000 32.783000 27.974000 33.277000 ;
 RECT 28.122000 32.783000 28.190000 33.277000 ;
 RECT 28.878000 32.805000 28.946000 33.323000 ;
 RECT 28.878000 31.117000 28.946000 31.635000 ;
 RECT 29.634000 31.163000 29.702000 31.657000 ;
 RECT 29.850000 31.163000 29.918000 31.657000 ;
 RECT 30.606000 31.117000 30.674000 31.635000 ;
 RECT 28.878000 32.805000 28.946000 33.323000 ;
 RECT 29.634000 32.783000 29.702000 33.277000 ;
 RECT 29.850000 32.783000 29.918000 33.277000 ;
 RECT 30.606000 32.805000 30.674000 33.323000 ;
 LAYER m2 ;
 RECT 76.864000 13.748000 78.160000 13.792000 ;
 RECT 76.864000 14.378000 78.028000 14.422000 ;
 RECT 76.888000 14.018000 78.088000 14.062000 ;
 RECT 76.888000 14.198000 78.088000 14.242000 ;
 RECT 77.256000 15.008000 78.160000 15.052000 ;
 RECT 77.591500 14.738000 78.088000 14.782000 ;
 RECT 30.588000 31.341000 32.420000 31.449000 ;
 RECT 30.588000 32.991000 32.420000 33.099000 ;
 RECT 32.316000 31.341000 34.148000 31.449000 ;
 RECT 32.316000 32.991000 34.148000 33.099000 ;
 RECT 34.044000 31.341000 35.876000 31.449000 ;
 RECT 34.044000 32.991000 35.876000 33.099000 ;
 RECT 35.772000 31.341000 37.604000 31.449000 ;
 RECT 35.772000 32.991000 37.604000 33.099000 ;
 RECT 37.500000 31.341000 39.332000 31.449000 ;
 RECT 37.500000 32.991000 39.332000 33.099000 ;
 RECT 76.864000 15.368000 78.160000 15.412000 ;
 RECT 76.864000 15.998000 78.028000 16.042000 ;
 RECT 76.888000 15.638000 78.088000 15.682000 ;
 RECT 76.888000 15.818000 78.088000 15.862000 ;
 RECT 77.256000 16.628000 78.160000 16.672000 ;
 RECT 77.591500 16.358000 78.088000 16.402000 ;
 RECT 39.228000 31.341000 41.060000 31.449000 ;
 RECT 39.228000 32.991000 41.060000 33.099000 ;
 RECT 40.956000 31.341000 42.788000 31.449000 ;
 RECT 40.956000 32.991000 42.788000 33.099000 ;
 RECT 42.684000 31.341000 44.516000 31.449000 ;
 RECT 42.684000 32.991000 44.516000 33.099000 ;
 RECT 44.412000 31.341000 46.244000 31.449000 ;
 RECT 44.412000 32.991000 46.244000 33.099000 ;
 RECT 46.140000 31.341000 47.972000 31.449000 ;
 RECT 46.140000 32.991000 47.972000 33.099000 ;
 RECT 76.864000 16.988000 78.160000 17.032000 ;
 RECT 76.864000 17.618000 78.028000 17.662000 ;
 RECT 76.888000 17.258000 78.088000 17.302000 ;
 RECT 76.888000 17.438000 78.088000 17.482000 ;
 RECT 77.256000 18.248000 78.160000 18.292000 ;
 RECT 77.591500 17.978000 78.088000 18.022000 ;
 RECT 47.868000 31.341000 49.700000 31.449000 ;
 RECT 47.868000 32.991000 49.700000 33.099000 ;
 RECT 49.596000 31.341000 51.428000 31.449000 ;
 RECT 49.596000 32.991000 51.428000 33.099000 ;
 RECT 51.324000 31.341000 53.156000 31.449000 ;
 RECT 51.324000 32.991000 53.156000 33.099000 ;
 RECT 53.052000 31.341000 54.884000 31.449000 ;
 RECT 53.052000 32.991000 54.884000 33.099000 ;
 RECT 54.780000 31.341000 56.612000 31.449000 ;
 RECT 54.780000 32.991000 56.612000 33.099000 ;
 RECT 76.864000 18.608000 78.160000 18.652000 ;
 RECT 76.864000 19.238000 78.028000 19.282000 ;
 RECT 76.888000 18.878000 78.088000 18.922000 ;
 RECT 76.888000 19.058000 78.088000 19.102000 ;
 RECT 77.256000 19.868000 78.160000 19.912000 ;
 RECT 77.591500 19.598000 78.088000 19.642000 ;
 RECT 81.888000 31.341000 83.720000 31.449000 ;
 RECT 81.888000 32.991000 83.720000 33.099000 ;
 RECT 83.616000 31.341000 85.448000 31.449000 ;
 RECT 83.616000 32.991000 85.448000 33.099000 ;
 RECT 85.344000 31.341000 87.176000 31.449000 ;
 RECT 85.344000 32.991000 87.176000 33.099000 ;
 RECT 87.072000 31.341000 88.904000 31.449000 ;
 RECT 87.072000 32.991000 88.904000 33.099000 ;
 RECT 88.800000 31.341000 90.632000 31.449000 ;
 RECT 88.800000 32.991000 90.632000 33.099000 ;
 RECT 76.864000 20.228000 78.160000 20.272000 ;
 RECT 76.864000 20.858000 78.028000 20.902000 ;
 RECT 76.888000 20.498000 78.088000 20.542000 ;
 RECT 76.888000 20.678000 78.088000 20.722000 ;
 RECT 77.256000 21.488000 78.160000 21.532000 ;
 RECT 77.591500 21.218000 78.088000 21.262000 ;
 RECT 90.528000 31.341000 92.360000 31.449000 ;
 RECT 90.528000 32.991000 92.360000 33.099000 ;
 RECT 92.256000 31.341000 94.088000 31.449000 ;
 RECT 92.256000 32.991000 94.088000 33.099000 ;
 RECT 93.984000 31.341000 95.816000 31.449000 ;
 RECT 93.984000 32.991000 95.816000 33.099000 ;
 RECT 95.712000 31.341000 97.544000 31.449000 ;
 RECT 95.712000 32.991000 97.544000 33.099000 ;
 RECT 97.440000 31.341000 99.272000 31.449000 ;
 RECT 97.440000 32.991000 99.272000 33.099000 ;
 RECT 76.864000 21.848000 78.160000 21.892000 ;
 RECT 76.864000 22.478000 78.028000 22.522000 ;
 RECT 76.888000 22.118000 78.088000 22.162000 ;
 RECT 76.888000 22.298000 78.088000 22.342000 ;
 RECT 77.256000 23.108000 78.160000 23.152000 ;
 RECT 77.591500 22.838000 78.088000 22.882000 ;
 RECT 99.168000 31.341000 101.000000 31.449000 ;
 RECT 99.168000 32.991000 101.000000 33.099000 ;
 RECT 100.896000 31.341000 102.728000 31.449000 ;
 RECT 100.896000 32.991000 102.728000 33.099000 ;
 RECT 102.624000 31.341000 104.456000 31.449000 ;
 RECT 102.624000 32.991000 104.456000 33.099000 ;
 RECT 104.352000 31.341000 106.184000 31.449000 ;
 RECT 104.352000 32.991000 106.184000 33.099000 ;
 RECT 106.080000 31.341000 107.912000 31.449000 ;
 RECT 106.080000 32.991000 107.912000 33.099000 ;
 RECT 76.864000 23.468000 78.160000 23.512000 ;
 RECT 76.864000 24.098000 78.028000 24.142000 ;
 RECT 76.888000 23.738000 78.088000 23.782000 ;
 RECT 76.888000 23.918000 78.088000 23.962000 ;
 RECT 77.256000 24.728000 78.160000 24.772000 ;
 RECT 77.591500 24.458000 78.088000 24.502000 ;
 RECT 107.808000 31.341000 109.640000 31.449000 ;
 RECT 107.808000 32.991000 109.640000 33.099000 ;
 RECT 109.536000 31.341000 111.368000 31.449000 ;
 RECT 109.536000 32.991000 111.368000 33.099000 ;
 RECT 111.264000 31.341000 113.096000 31.449000 ;
 RECT 111.264000 32.991000 113.096000 33.099000 ;
 RECT 112.992000 31.341000 114.824000 31.449000 ;
 RECT 112.992000 32.991000 114.824000 33.099000 ;
 RECT 114.720000 31.341000 116.552000 31.449000 ;
 RECT 114.720000 32.991000 116.552000 33.099000 ;
 RECT 76.864000 25.088000 78.160000 25.132000 ;
 RECT 76.864000 25.718000 78.028000 25.762000 ;
 RECT 76.888000 25.358000 78.088000 25.402000 ;
 RECT 76.888000 25.538000 78.088000 25.582000 ;
 RECT 77.256000 26.348000 78.160000 26.392000 ;
 RECT 77.591500 26.078000 78.088000 26.122000 ;
 RECT 116.448000 31.341000 118.280000 31.449000 ;
 RECT 116.448000 32.991000 118.280000 33.099000 ;
 RECT 118.176000 31.341000 120.008000 31.449000 ;
 RECT 118.176000 32.991000 120.008000 33.099000 ;
 RECT 119.904000 31.341000 121.736000 31.449000 ;
 RECT 119.904000 32.991000 121.736000 33.099000 ;
 RECT 121.632000 31.341000 123.464000 31.449000 ;
 RECT 121.632000 32.991000 123.464000 33.099000 ;
 RECT 123.360000 31.341000 125.192000 31.449000 ;
 RECT 123.360000 32.991000 125.192000 33.099000 ;
 RECT 76.864000 39.308000 78.160000 39.352000 ;
 RECT 76.864000 39.938000 78.028000 39.982000 ;
 RECT 76.888000 39.578000 78.088000 39.622000 ;
 RECT 76.888000 39.758000 78.088000 39.802000 ;
 RECT 77.256000 40.568000 78.160000 40.612000 ;
 RECT 77.591500 40.298000 78.088000 40.342000 ;
 RECT 125.088000 31.341000 126.920000 31.449000 ;
 RECT 125.088000 32.991000 126.920000 33.099000 ;
 RECT 126.816000 31.341000 128.648000 31.449000 ;
 RECT 126.816000 32.991000 128.648000 33.099000 ;
 RECT 128.544000 31.341000 130.376000 31.449000 ;
 RECT 128.544000 32.991000 130.376000 33.099000 ;
 RECT 130.272000 31.341000 132.104000 31.449000 ;
 RECT 130.272000 32.991000 132.104000 33.099000 ;
 RECT 132.000000 31.341000 133.832000 31.449000 ;
 RECT 132.000000 32.991000 133.832000 33.099000 ;
 RECT 76.864000 40.928000 78.160000 40.972000 ;
 RECT 76.864000 41.558000 78.028000 41.602000 ;
 RECT 76.888000 41.198000 78.088000 41.242000 ;
 RECT 76.888000 41.378000 78.088000 41.422000 ;
 RECT 77.256000 42.188000 78.160000 42.232000 ;
 RECT 77.591500 41.918000 78.088000 41.962000 ;
 RECT 133.728000 31.341000 135.560000 31.449000 ;
 RECT 133.728000 32.991000 135.560000 33.099000 ;
 RECT 135.456000 31.341000 137.288000 31.449000 ;
 RECT 135.456000 32.991000 137.288000 33.099000 ;
 RECT 59.640000 28.778000 60.640000 28.822000 ;
 RECT 59.856000 28.418000 60.711000 28.462000 ;
 RECT 59.640000 30.038000 60.640000 30.082000 ;
 RECT 59.856000 29.678000 60.711000 29.722000 ;
 RECT 59.640000 31.298000 60.640000 31.342000 ;
 RECT 59.856000 30.938000 60.711000 30.982000 ;
 RECT 59.640000 32.558000 60.640000 32.602000 ;
 RECT 59.856000 32.198000 60.711000 32.242000 ;
 RECT 59.640000 33.818000 60.640000 33.862000 ;
 RECT 59.856000 33.458000 60.711000 33.502000 ;
 RECT 59.640000 35.078000 60.640000 35.122000 ;
 RECT 59.856000 34.718000 60.711000 34.762000 ;
 RECT 76.864000 0.788000 78.160000 0.832000 ;
 RECT 76.864000 1.418000 78.028000 1.462000 ;
 RECT 76.888000 1.058000 78.088000 1.102000 ;
 RECT 76.888000 1.238000 78.088000 1.282000 ;
 RECT 77.256000 2.048000 78.160000 2.092000 ;
 RECT 77.591500 1.778000 78.088000 1.822000 ;
 RECT 76.864000 42.548000 78.160000 42.592000 ;
 RECT 76.864000 43.178000 78.028000 43.222000 ;
 RECT 76.888000 42.818000 78.088000 42.862000 ;
 RECT 76.888000 42.998000 78.088000 43.042000 ;
 RECT 77.256000 43.808000 78.160000 43.852000 ;
 RECT 77.591500 43.538000 78.088000 43.582000 ;
 RECT 59.640000 36.338000 60.640000 36.382000 ;
 RECT 59.856000 35.978000 60.711000 36.022000 ;
 RECT 59.640000 37.598000 60.640000 37.642000 ;
 RECT 59.856000 37.238000 60.711000 37.282000 ;
 RECT 77.860000 28.058000 78.860000 28.102000 ;
 RECT 77.789000 28.418000 78.644000 28.462000 ;
 RECT 77.860000 29.318000 78.860000 29.362000 ;
 RECT 77.789000 29.678000 78.644000 29.722000 ;
 RECT 77.860000 30.578000 78.860000 30.622000 ;
 RECT 77.789000 30.938000 78.644000 30.982000 ;
 RECT 77.860000 31.838000 78.860000 31.882000 ;
 RECT 77.789000 32.198000 78.644000 32.242000 ;
 RECT 77.860000 33.098000 78.860000 33.142000 ;
 RECT 77.789000 33.458000 78.644000 33.502000 ;
 RECT 77.860000 34.358000 78.860000 34.402000 ;
 RECT 77.789000 34.718000 78.644000 34.762000 ;
 RECT 77.860000 35.618000 78.860000 35.662000 ;
 RECT 77.789000 35.978000 78.644000 36.022000 ;
 RECT 77.860000 36.878000 78.860000 36.922000 ;
 RECT 77.789000 37.238000 78.644000 37.282000 ;
 RECT 76.864000 44.168000 78.160000 44.212000 ;
 RECT 76.864000 44.798000 78.028000 44.842000 ;
 RECT 76.888000 44.438000 78.088000 44.482000 ;
 RECT 76.888000 44.618000 78.088000 44.662000 ;
 RECT 77.256000 45.428000 78.160000 45.472000 ;
 RECT 77.591500 45.158000 78.088000 45.202000 ;
 RECT 76.864000 45.788000 78.160000 45.832000 ;
 RECT 76.864000 46.418000 78.028000 46.462000 ;
 RECT 76.888000 46.058000 78.088000 46.102000 ;
 RECT 76.888000 46.238000 78.088000 46.282000 ;
 RECT 77.256000 47.048000 78.160000 47.092000 ;
 RECT 77.591500 46.778000 78.088000 46.822000 ;
 RECT 76.864000 47.408000 78.160000 47.452000 ;
 RECT 76.864000 48.038000 78.028000 48.082000 ;
 RECT 76.888000 47.678000 78.088000 47.722000 ;
 RECT 76.888000 47.858000 78.088000 47.902000 ;
 RECT 77.256000 48.668000 78.160000 48.712000 ;
 RECT 77.591500 48.398000 78.088000 48.442000 ;
 RECT 76.864000 49.028000 78.160000 49.072000 ;
 RECT 76.864000 49.658000 78.028000 49.702000 ;
 RECT 76.888000 49.298000 78.088000 49.342000 ;
 RECT 76.888000 49.478000 78.088000 49.522000 ;
 RECT 77.256000 50.288000 78.160000 50.332000 ;
 RECT 77.591500 50.018000 78.088000 50.062000 ;
 RECT 76.864000 50.648000 78.160000 50.692000 ;
 RECT 76.864000 51.278000 78.028000 51.322000 ;
 RECT 76.888000 50.918000 78.088000 50.962000 ;
 RECT 76.888000 51.098000 78.088000 51.142000 ;
 RECT 77.256000 51.908000 78.160000 51.952000 ;
 RECT 77.591500 51.638000 78.088000 51.682000 ;
 RECT 76.864000 52.268000 78.160000 52.312000 ;
 RECT 76.864000 52.898000 78.028000 52.942000 ;
 RECT 76.888000 52.538000 78.088000 52.582000 ;
 RECT 76.888000 52.718000 78.088000 52.762000 ;
 RECT 77.256000 53.528000 78.160000 53.572000 ;
 RECT 77.591500 53.258000 78.088000 53.302000 ;
 RECT 76.864000 53.888000 78.160000 53.932000 ;
 RECT 76.864000 54.518000 78.028000 54.562000 ;
 RECT 76.888000 54.158000 78.088000 54.202000 ;
 RECT 76.888000 54.338000 78.088000 54.382000 ;
 RECT 77.256000 55.148000 78.160000 55.192000 ;
 RECT 77.591500 54.878000 78.088000 54.922000 ;
 RECT 76.864000 55.508000 78.160000 55.552000 ;
 RECT 76.864000 56.138000 78.028000 56.182000 ;
 RECT 76.888000 55.778000 78.088000 55.822000 ;
 RECT 76.888000 55.958000 78.088000 56.002000 ;
 RECT 77.256000 56.768000 78.160000 56.812000 ;
 RECT 77.591500 56.498000 78.088000 56.542000 ;
 RECT 76.864000 57.128000 78.160000 57.172000 ;
 RECT 76.864000 57.758000 78.028000 57.802000 ;
 RECT 76.888000 57.398000 78.088000 57.442000 ;
 RECT 76.888000 57.578000 78.088000 57.622000 ;
 RECT 77.256000 58.388000 78.160000 58.432000 ;
 RECT 77.591500 58.118000 78.088000 58.162000 ;
 RECT 76.864000 2.408000 78.160000 2.452000 ;
 RECT 76.864000 3.038000 78.028000 3.082000 ;
 RECT 76.888000 2.678000 78.088000 2.722000 ;
 RECT 76.888000 2.858000 78.088000 2.902000 ;
 RECT 77.256000 3.668000 78.160000 3.712000 ;
 RECT 77.591500 3.398000 78.088000 3.442000 ;
 RECT 76.864000 58.748000 78.160000 58.792000 ;
 RECT 76.864000 59.378000 78.028000 59.422000 ;
 RECT 76.888000 59.018000 78.088000 59.062000 ;
 RECT 76.888000 59.198000 78.088000 59.242000 ;
 RECT 77.256000 60.008000 78.160000 60.052000 ;
 RECT 77.591500 59.738000 78.088000 59.782000 ;
 RECT 76.864000 60.368000 78.160000 60.412000 ;
 RECT 76.864000 60.998000 78.028000 61.042000 ;
 RECT 76.888000 60.638000 78.088000 60.682000 ;
 RECT 76.888000 60.818000 78.088000 60.862000 ;
 RECT 77.256000 61.628000 78.160000 61.672000 ;
 RECT 77.591500 61.358000 78.088000 61.402000 ;
 RECT 76.864000 61.988000 78.160000 62.032000 ;
 RECT 76.864000 62.618000 78.028000 62.662000 ;
 RECT 76.888000 62.258000 78.088000 62.302000 ;
 RECT 76.888000 62.438000 78.088000 62.482000 ;
 RECT 77.256000 63.248000 78.160000 63.292000 ;
 RECT 77.591500 62.978000 78.088000 63.022000 ;
 RECT 76.864000 63.608000 78.160000 63.652000 ;
 RECT 76.864000 64.238000 78.028000 64.282000 ;
 RECT 76.888000 63.878000 78.088000 63.922000 ;
 RECT 76.888000 64.058000 78.088000 64.102000 ;
 RECT 77.256000 64.868000 78.160000 64.912000 ;
 RECT 77.591500 64.598000 78.088000 64.642000 ;
 RECT 60.340000 0.788000 61.244000 0.832000 ;
 RECT 60.340000 2.048000 61.636000 2.092000 ;
 RECT 60.412000 1.058000 60.908500 1.102000 ;
 RECT 60.412000 1.598000 61.612000 1.642000 ;
 RECT 60.412000 1.778000 61.612000 1.822000 ;
 RECT 60.472000 1.418000 61.636000 1.462000 ;
 RECT 60.340000 2.408000 61.244000 2.452000 ;
 RECT 60.340000 3.668000 61.636000 3.712000 ;
 RECT 60.412000 2.678000 60.908500 2.722000 ;
 RECT 60.412000 3.218000 61.612000 3.262000 ;
 RECT 60.412000 3.398000 61.612000 3.442000 ;
 RECT 60.472000 3.038000 61.636000 3.082000 ;
 RECT 60.340000 4.028000 61.244000 4.072000 ;
 RECT 60.340000 5.288000 61.636000 5.332000 ;
 RECT 60.412000 4.298000 60.908500 4.342000 ;
 RECT 60.412000 4.838000 61.612000 4.882000 ;
 RECT 60.412000 5.018000 61.612000 5.062000 ;
 RECT 60.472000 4.658000 61.636000 4.702000 ;
 RECT 60.340000 5.648000 61.244000 5.692000 ;
 RECT 60.340000 6.908000 61.636000 6.952000 ;
 RECT 60.412000 5.918000 60.908500 5.962000 ;
 RECT 60.412000 6.458000 61.612000 6.502000 ;
 RECT 60.412000 6.638000 61.612000 6.682000 ;
 RECT 60.472000 6.278000 61.636000 6.322000 ;
 RECT 60.340000 7.268000 61.244000 7.312000 ;
 RECT 60.340000 8.528000 61.636000 8.572000 ;
 RECT 60.412000 7.538000 60.908500 7.582000 ;
 RECT 60.412000 8.078000 61.612000 8.122000 ;
 RECT 60.412000 8.258000 61.612000 8.302000 ;
 RECT 60.472000 7.898000 61.636000 7.942000 ;
 RECT 60.340000 8.888000 61.244000 8.932000 ;
 RECT 60.340000 10.148000 61.636000 10.192000 ;
 RECT 60.412000 9.158000 60.908500 9.202000 ;
 RECT 60.412000 9.698000 61.612000 9.742000 ;
 RECT 60.412000 9.878000 61.612000 9.922000 ;
 RECT 60.472000 9.518000 61.636000 9.562000 ;
 RECT 76.864000 4.028000 78.160000 4.072000 ;
 RECT 76.864000 4.658000 78.028000 4.702000 ;
 RECT 76.888000 4.298000 78.088000 4.342000 ;
 RECT 76.888000 4.478000 78.088000 4.522000 ;
 RECT 77.256000 5.288000 78.160000 5.332000 ;
 RECT 77.591500 5.018000 78.088000 5.062000 ;
 RECT 60.340000 10.508000 61.244000 10.552000 ;
 RECT 60.340000 11.768000 61.636000 11.812000 ;
 RECT 60.412000 10.778000 60.908500 10.822000 ;
 RECT 60.412000 11.318000 61.612000 11.362000 ;
 RECT 60.412000 11.498000 61.612000 11.542000 ;
 RECT 60.472000 11.138000 61.636000 11.182000 ;
 RECT 60.340000 12.128000 61.244000 12.172000 ;
 RECT 60.340000 13.388000 61.636000 13.432000 ;
 RECT 60.412000 12.398000 60.908500 12.442000 ;
 RECT 60.412000 12.938000 61.612000 12.982000 ;
 RECT 60.412000 13.118000 61.612000 13.162000 ;
 RECT 60.472000 12.758000 61.636000 12.802000 ;
 RECT 60.340000 13.748000 61.244000 13.792000 ;
 RECT 60.340000 15.008000 61.636000 15.052000 ;
 RECT 60.412000 14.018000 60.908500 14.062000 ;
 RECT 60.412000 14.558000 61.612000 14.602000 ;
 RECT 60.412000 14.738000 61.612000 14.782000 ;
 RECT 60.472000 14.378000 61.636000 14.422000 ;
 RECT 60.340000 15.368000 61.244000 15.412000 ;
 RECT 60.340000 16.628000 61.636000 16.672000 ;
 RECT 60.412000 15.638000 60.908500 15.682000 ;
 RECT 60.412000 16.178000 61.612000 16.222000 ;
 RECT 60.412000 16.358000 61.612000 16.402000 ;
 RECT 60.472000 15.998000 61.636000 16.042000 ;
 RECT 60.340000 16.988000 61.244000 17.032000 ;
 RECT 60.340000 18.248000 61.636000 18.292000 ;
 RECT 60.412000 17.258000 60.908500 17.302000 ;
 RECT 60.412000 17.798000 61.612000 17.842000 ;
 RECT 60.412000 17.978000 61.612000 18.022000 ;
 RECT 60.472000 17.618000 61.636000 17.662000 ;
 RECT 60.340000 18.608000 61.244000 18.652000 ;
 RECT 60.340000 19.868000 61.636000 19.912000 ;
 RECT 60.412000 18.878000 60.908500 18.922000 ;
 RECT 60.412000 19.418000 61.612000 19.462000 ;
 RECT 60.412000 19.598000 61.612000 19.642000 ;
 RECT 60.472000 19.238000 61.636000 19.282000 ;
 RECT 60.340000 20.228000 61.244000 20.272000 ;
 RECT 60.340000 21.488000 61.636000 21.532000 ;
 RECT 60.412000 20.498000 60.908500 20.542000 ;
 RECT 60.412000 21.038000 61.612000 21.082000 ;
 RECT 60.412000 21.218000 61.612000 21.262000 ;
 RECT 60.472000 20.858000 61.636000 20.902000 ;
 RECT 60.340000 21.848000 61.244000 21.892000 ;
 RECT 60.340000 23.108000 61.636000 23.152000 ;
 RECT 60.412000 22.118000 60.908500 22.162000 ;
 RECT 60.412000 22.658000 61.612000 22.702000 ;
 RECT 60.412000 22.838000 61.612000 22.882000 ;
 RECT 60.472000 22.478000 61.636000 22.522000 ;
 RECT 60.340000 23.468000 61.244000 23.512000 ;
 RECT 60.340000 24.728000 61.636000 24.772000 ;
 RECT 60.412000 23.738000 60.908500 23.782000 ;
 RECT 60.412000 24.278000 61.612000 24.322000 ;
 RECT 60.412000 24.458000 61.612000 24.502000 ;
 RECT 60.472000 24.098000 61.636000 24.142000 ;
 RECT 60.340000 25.088000 61.244000 25.132000 ;
 RECT 60.340000 26.348000 61.636000 26.392000 ;
 RECT 60.412000 25.358000 60.908500 25.402000 ;
 RECT 60.412000 25.898000 61.612000 25.942000 ;
 RECT 60.412000 26.078000 61.612000 26.122000 ;
 RECT 60.472000 25.718000 61.636000 25.762000 ;
 RECT 76.864000 5.648000 78.160000 5.692000 ;
 RECT 76.864000 6.278000 78.028000 6.322000 ;
 RECT 76.888000 5.918000 78.088000 5.962000 ;
 RECT 76.888000 6.098000 78.088000 6.142000 ;
 RECT 77.256000 6.908000 78.160000 6.952000 ;
 RECT 77.591500 6.638000 78.088000 6.682000 ;
 RECT 60.340000 39.308000 61.244000 39.352000 ;
 RECT 60.340000 40.568000 61.636000 40.612000 ;
 RECT 60.412000 39.578000 60.908500 39.622000 ;
 RECT 60.412000 40.118000 61.612000 40.162000 ;
 RECT 60.412000 40.298000 61.612000 40.342000 ;
 RECT 60.472000 39.938000 61.636000 39.982000 ;
 RECT 60.340000 40.928000 61.244000 40.972000 ;
 RECT 60.340000 42.188000 61.636000 42.232000 ;
 RECT 60.412000 41.198000 60.908500 41.242000 ;
 RECT 60.412000 41.738000 61.612000 41.782000 ;
 RECT 60.412000 41.918000 61.612000 41.962000 ;
 RECT 60.472000 41.558000 61.636000 41.602000 ;
 RECT 60.340000 42.548000 61.244000 42.592000 ;
 RECT 60.340000 43.808000 61.636000 43.852000 ;
 RECT 60.412000 42.818000 60.908500 42.862000 ;
 RECT 60.412000 43.358000 61.612000 43.402000 ;
 RECT 60.412000 43.538000 61.612000 43.582000 ;
 RECT 60.472000 43.178000 61.636000 43.222000 ;
 RECT 60.340000 44.168000 61.244000 44.212000 ;
 RECT 60.340000 45.428000 61.636000 45.472000 ;
 RECT 60.412000 44.438000 60.908500 44.482000 ;
 RECT 60.412000 44.978000 61.612000 45.022000 ;
 RECT 60.412000 45.158000 61.612000 45.202000 ;
 RECT 60.472000 44.798000 61.636000 44.842000 ;
 RECT 60.340000 45.788000 61.244000 45.832000 ;
 RECT 60.340000 47.048000 61.636000 47.092000 ;
 RECT 60.412000 46.058000 60.908500 46.102000 ;
 RECT 60.412000 46.598000 61.612000 46.642000 ;
 RECT 60.412000 46.778000 61.612000 46.822000 ;
 RECT 60.472000 46.418000 61.636000 46.462000 ;
 RECT 60.340000 47.408000 61.244000 47.452000 ;
 RECT 60.340000 48.668000 61.636000 48.712000 ;
 RECT 60.412000 47.678000 60.908500 47.722000 ;
 RECT 60.412000 48.218000 61.612000 48.262000 ;
 RECT 60.412000 48.398000 61.612000 48.442000 ;
 RECT 60.472000 48.038000 61.636000 48.082000 ;
 RECT 60.340000 49.028000 61.244000 49.072000 ;
 RECT 60.340000 50.288000 61.636000 50.332000 ;
 RECT 60.412000 49.298000 60.908500 49.342000 ;
 RECT 60.412000 49.838000 61.612000 49.882000 ;
 RECT 60.412000 50.018000 61.612000 50.062000 ;
 RECT 60.472000 49.658000 61.636000 49.702000 ;
 RECT 60.340000 50.648000 61.244000 50.692000 ;
 RECT 60.340000 51.908000 61.636000 51.952000 ;
 RECT 60.412000 50.918000 60.908500 50.962000 ;
 RECT 60.412000 51.458000 61.612000 51.502000 ;
 RECT 60.412000 51.638000 61.612000 51.682000 ;
 RECT 60.472000 51.278000 61.636000 51.322000 ;
 RECT 60.340000 52.268000 61.244000 52.312000 ;
 RECT 60.340000 53.528000 61.636000 53.572000 ;
 RECT 60.412000 52.538000 60.908500 52.582000 ;
 RECT 60.412000 53.078000 61.612000 53.122000 ;
 RECT 60.412000 53.258000 61.612000 53.302000 ;
 RECT 60.472000 52.898000 61.636000 52.942000 ;
 RECT 60.340000 53.888000 61.244000 53.932000 ;
 RECT 60.340000 55.148000 61.636000 55.192000 ;
 RECT 60.412000 54.158000 60.908500 54.202000 ;
 RECT 60.412000 54.698000 61.612000 54.742000 ;
 RECT 60.412000 54.878000 61.612000 54.922000 ;
 RECT 60.472000 54.518000 61.636000 54.562000 ;
 RECT 76.864000 7.268000 78.160000 7.312000 ;
 RECT 76.864000 7.898000 78.028000 7.942000 ;
 RECT 76.888000 7.538000 78.088000 7.582000 ;
 RECT 76.888000 7.718000 78.088000 7.762000 ;
 RECT 77.256000 8.528000 78.160000 8.572000 ;
 RECT 77.591500 8.258000 78.088000 8.302000 ;
 RECT 60.340000 55.508000 61.244000 55.552000 ;
 RECT 60.340000 56.768000 61.636000 56.812000 ;
 RECT 60.412000 55.778000 60.908500 55.822000 ;
 RECT 60.412000 56.318000 61.612000 56.362000 ;
 RECT 60.412000 56.498000 61.612000 56.542000 ;
 RECT 60.472000 56.138000 61.636000 56.182000 ;
 RECT 60.340000 57.128000 61.244000 57.172000 ;
 RECT 60.340000 58.388000 61.636000 58.432000 ;
 RECT 60.412000 57.398000 60.908500 57.442000 ;
 RECT 60.412000 57.938000 61.612000 57.982000 ;
 RECT 60.412000 58.118000 61.612000 58.162000 ;
 RECT 60.472000 57.758000 61.636000 57.802000 ;
 RECT 60.340000 58.748000 61.244000 58.792000 ;
 RECT 60.340000 60.008000 61.636000 60.052000 ;
 RECT 60.412000 59.018000 60.908500 59.062000 ;
 RECT 60.412000 59.558000 61.612000 59.602000 ;
 RECT 60.412000 59.738000 61.612000 59.782000 ;
 RECT 60.472000 59.378000 61.636000 59.422000 ;
 RECT 60.340000 60.368000 61.244000 60.412000 ;
 RECT 60.340000 61.628000 61.636000 61.672000 ;
 RECT 60.412000 60.638000 60.908500 60.682000 ;
 RECT 60.412000 61.178000 61.612000 61.222000 ;
 RECT 60.412000 61.358000 61.612000 61.402000 ;
 RECT 60.472000 60.998000 61.636000 61.042000 ;
 RECT 60.340000 61.988000 61.244000 62.032000 ;
 RECT 60.340000 63.248000 61.636000 63.292000 ;
 RECT 60.412000 62.258000 60.908500 62.302000 ;
 RECT 60.412000 62.798000 61.612000 62.842000 ;
 RECT 60.412000 62.978000 61.612000 63.022000 ;
 RECT 60.472000 62.618000 61.636000 62.662000 ;
 RECT 60.340000 63.608000 61.244000 63.652000 ;
 RECT 60.340000 64.868000 61.636000 64.912000 ;
 RECT 60.412000 63.878000 60.908500 63.922000 ;
 RECT 60.412000 64.418000 61.612000 64.462000 ;
 RECT 60.412000 64.598000 61.612000 64.642000 ;
 RECT 60.472000 64.238000 61.636000 64.282000 ;
 RECT 1.212000 31.341000 3.044000 31.449000 ;
 RECT 1.212000 32.991000 3.044000 33.099000 ;
 RECT 2.940000 31.341000 4.772000 31.449000 ;
 RECT 2.940000 32.991000 4.772000 33.099000 ;
 RECT 76.864000 8.888000 78.160000 8.932000 ;
 RECT 76.864000 9.518000 78.028000 9.562000 ;
 RECT 76.888000 9.158000 78.088000 9.202000 ;
 RECT 76.888000 9.338000 78.088000 9.382000 ;
 RECT 77.256000 10.148000 78.160000 10.192000 ;
 RECT 77.591500 9.878000 78.088000 9.922000 ;
 RECT 4.668000 31.341000 6.500000 31.449000 ;
 RECT 4.668000 32.991000 6.500000 33.099000 ;
 RECT 6.396000 31.341000 8.228000 31.449000 ;
 RECT 6.396000 32.991000 8.228000 33.099000 ;
 RECT 8.124000 31.341000 9.956000 31.449000 ;
 RECT 8.124000 32.991000 9.956000 33.099000 ;
 RECT 9.852000 31.341000 11.684000 31.449000 ;
 RECT 9.852000 32.991000 11.684000 33.099000 ;
 RECT 11.580000 31.341000 13.412000 31.449000 ;
 RECT 11.580000 32.991000 13.412000 33.099000 ;
 RECT 76.864000 10.508000 78.160000 10.552000 ;
 RECT 76.864000 11.138000 78.028000 11.182000 ;
 RECT 76.888000 10.778000 78.088000 10.822000 ;
 RECT 76.888000 10.958000 78.088000 11.002000 ;
 RECT 77.256000 11.768000 78.160000 11.812000 ;
 RECT 77.591500 11.498000 78.088000 11.542000 ;
 RECT 13.308000 31.341000 15.140000 31.449000 ;
 RECT 13.308000 32.991000 15.140000 33.099000 ;
 RECT 15.036000 31.341000 16.868000 31.449000 ;
 RECT 15.036000 32.991000 16.868000 33.099000 ;
 RECT 16.764000 31.341000 18.596000 31.449000 ;
 RECT 16.764000 32.991000 18.596000 33.099000 ;
 RECT 18.492000 31.341000 20.324000 31.449000 ;
 RECT 18.492000 32.991000 20.324000 33.099000 ;
 RECT 20.220000 31.341000 22.052000 31.449000 ;
 RECT 20.220000 32.991000 22.052000 33.099000 ;
 RECT 76.864000 12.128000 78.160000 12.172000 ;
 RECT 76.864000 12.758000 78.028000 12.802000 ;
 RECT 76.888000 12.398000 78.088000 12.442000 ;
 RECT 76.888000 12.578000 78.088000 12.622000 ;
 RECT 77.256000 13.388000 78.160000 13.432000 ;
 RECT 77.591500 13.118000 78.088000 13.162000 ;
 RECT 21.948000 31.341000 23.780000 31.449000 ;
 RECT 21.948000 32.991000 23.780000 33.099000 ;
 RECT 23.676000 31.341000 25.508000 31.449000 ;
 RECT 23.676000 32.991000 25.508000 33.099000 ;
 RECT 25.404000 31.341000 27.236000 31.449000 ;
 RECT 25.404000 32.991000 27.236000 33.099000 ;
 RECT 27.132000 31.341000 28.964000 31.449000 ;
 RECT 27.132000 32.991000 28.964000 33.099000 ;
 RECT 28.860000 31.341000 30.692000 31.449000 ;
 RECT 28.860000 32.991000 30.692000 33.099000 ;
 LAYER m3 ;
 RECT 77.268000 13.590000 77.344000 15.210000 ;
 RECT 77.512000 13.590000 77.588000 15.210000 ;
 RECT 77.756000 13.590000 77.832000 15.210000 ;
 RECT 78.000000 13.590000 78.076000 15.210000 ;
 RECT 77.268000 15.210000 77.344000 16.830000 ;
 RECT 77.512000 15.210000 77.588000 16.830000 ;
 RECT 77.756000 15.210000 77.832000 16.830000 ;
 RECT 78.000000 15.210000 78.076000 16.830000 ;
 RECT 77.268000 16.830000 77.344000 18.450000 ;
 RECT 77.512000 16.830000 77.588000 18.450000 ;
 RECT 77.756000 16.830000 77.832000 18.450000 ;
 RECT 78.000000 16.830000 78.076000 18.450000 ;
 RECT 77.268000 18.450000 77.344000 20.070000 ;
 RECT 77.512000 18.450000 77.588000 20.070000 ;
 RECT 77.756000 18.450000 77.832000 20.070000 ;
 RECT 78.000000 18.450000 78.076000 20.070000 ;
 RECT 77.268000 20.070000 77.344000 21.690000 ;
 RECT 77.512000 20.070000 77.588000 21.690000 ;
 RECT 77.756000 20.070000 77.832000 21.690000 ;
 RECT 78.000000 20.070000 78.076000 21.690000 ;
 RECT 77.268000 21.690000 77.344000 23.310000 ;
 RECT 77.512000 21.690000 77.588000 23.310000 ;
 RECT 77.756000 21.690000 77.832000 23.310000 ;
 RECT 78.000000 21.690000 78.076000 23.310000 ;
 RECT 77.268000 23.310000 77.344000 24.930000 ;
 RECT 77.512000 23.310000 77.588000 24.930000 ;
 RECT 77.756000 23.310000 77.832000 24.930000 ;
 RECT 78.000000 23.310000 78.076000 24.930000 ;
 RECT 77.268000 24.930000 77.344000 26.550000 ;
 RECT 77.512000 24.930000 77.588000 26.550000 ;
 RECT 77.756000 24.930000 77.832000 26.550000 ;
 RECT 78.000000 24.930000 78.076000 26.550000 ;
 RECT 77.268000 39.150000 77.344000 40.770000 ;
 RECT 77.512000 39.150000 77.588000 40.770000 ;
 RECT 77.756000 39.150000 77.832000 40.770000 ;
 RECT 78.000000 39.150000 78.076000 40.770000 ;
 RECT 77.268000 40.770000 77.344000 42.390000 ;
 RECT 77.512000 40.770000 77.588000 42.390000 ;
 RECT 77.756000 40.770000 77.832000 42.390000 ;
 RECT 78.000000 40.770000 78.076000 42.390000 ;
 RECT 77.268000 0.630000 77.344000 2.250000 ;
 RECT 77.512000 0.630000 77.588000 2.250000 ;
 RECT 77.756000 0.630000 77.832000 2.250000 ;
 RECT 78.000000 0.630000 78.076000 2.250000 ;
 RECT 77.268000 42.390000 77.344000 44.010000 ;
 RECT 77.512000 42.390000 77.588000 44.010000 ;
 RECT 77.756000 42.390000 77.832000 44.010000 ;
 RECT 78.000000 42.390000 78.076000 44.010000 ;
 RECT 77.268000 44.010000 77.344000 45.630000 ;
 RECT 77.512000 44.010000 77.588000 45.630000 ;
 RECT 77.756000 44.010000 77.832000 45.630000 ;
 RECT 78.000000 44.010000 78.076000 45.630000 ;
 RECT 77.268000 45.630000 77.344000 47.250000 ;
 RECT 77.512000 45.630000 77.588000 47.250000 ;
 RECT 77.756000 45.630000 77.832000 47.250000 ;
 RECT 78.000000 45.630000 78.076000 47.250000 ;
 RECT 77.268000 47.250000 77.344000 48.870000 ;
 RECT 77.512000 47.250000 77.588000 48.870000 ;
 RECT 77.756000 47.250000 77.832000 48.870000 ;
 RECT 78.000000 47.250000 78.076000 48.870000 ;
 RECT 77.268000 48.870000 77.344000 50.490000 ;
 RECT 77.512000 48.870000 77.588000 50.490000 ;
 RECT 77.756000 48.870000 77.832000 50.490000 ;
 RECT 78.000000 48.870000 78.076000 50.490000 ;
 RECT 77.268000 50.490000 77.344000 52.110000 ;
 RECT 77.512000 50.490000 77.588000 52.110000 ;
 RECT 77.756000 50.490000 77.832000 52.110000 ;
 RECT 78.000000 50.490000 78.076000 52.110000 ;
 RECT 77.268000 52.110000 77.344000 53.730000 ;
 RECT 77.512000 52.110000 77.588000 53.730000 ;
 RECT 77.756000 52.110000 77.832000 53.730000 ;
 RECT 78.000000 52.110000 78.076000 53.730000 ;
 RECT 77.268000 53.730000 77.344000 55.350000 ;
 RECT 77.512000 53.730000 77.588000 55.350000 ;
 RECT 77.756000 53.730000 77.832000 55.350000 ;
 RECT 78.000000 53.730000 78.076000 55.350000 ;
 RECT 77.268000 55.350000 77.344000 56.970000 ;
 RECT 77.512000 55.350000 77.588000 56.970000 ;
 RECT 77.756000 55.350000 77.832000 56.970000 ;
 RECT 78.000000 55.350000 78.076000 56.970000 ;
 RECT 77.268000 56.970000 77.344000 58.590000 ;
 RECT 77.512000 56.970000 77.588000 58.590000 ;
 RECT 77.756000 56.970000 77.832000 58.590000 ;
 RECT 78.000000 56.970000 78.076000 58.590000 ;
 RECT 77.268000 2.250000 77.344000 3.870000 ;
 RECT 77.512000 2.250000 77.588000 3.870000 ;
 RECT 77.756000 2.250000 77.832000 3.870000 ;
 RECT 78.000000 2.250000 78.076000 3.870000 ;
 RECT 77.268000 58.590000 77.344000 60.210000 ;
 RECT 77.512000 58.590000 77.588000 60.210000 ;
 RECT 77.756000 58.590000 77.832000 60.210000 ;
 RECT 78.000000 58.590000 78.076000 60.210000 ;
 RECT 77.268000 60.210000 77.344000 61.830000 ;
 RECT 77.512000 60.210000 77.588000 61.830000 ;
 RECT 77.756000 60.210000 77.832000 61.830000 ;
 RECT 78.000000 60.210000 78.076000 61.830000 ;
 RECT 77.268000 61.830000 77.344000 63.450000 ;
 RECT 77.512000 61.830000 77.588000 63.450000 ;
 RECT 77.756000 61.830000 77.832000 63.450000 ;
 RECT 78.000000 61.830000 78.076000 63.450000 ;
 RECT 77.268000 63.450000 77.344000 65.070000 ;
 RECT 77.512000 63.450000 77.588000 65.070000 ;
 RECT 77.756000 63.450000 77.832000 65.070000 ;
 RECT 78.000000 63.450000 78.076000 65.070000 ;
 RECT 60.424000 0.630000 60.500000 2.250000 ;
 RECT 60.668000 0.630000 60.744000 2.250000 ;
 RECT 60.912000 0.630000 60.988000 2.250000 ;
 RECT 61.156000 0.630000 61.232000 2.250000 ;
 RECT 60.424000 2.250000 60.500000 3.870000 ;
 RECT 60.668000 2.250000 60.744000 3.870000 ;
 RECT 60.912000 2.250000 60.988000 3.870000 ;
 RECT 61.156000 2.250000 61.232000 3.870000 ;
 RECT 60.424000 3.870000 60.500000 5.490000 ;
 RECT 60.668000 3.870000 60.744000 5.490000 ;
 RECT 60.912000 3.870000 60.988000 5.490000 ;
 RECT 61.156000 3.870000 61.232000 5.490000 ;
 RECT 60.424000 5.490000 60.500000 7.110000 ;
 RECT 60.668000 5.490000 60.744000 7.110000 ;
 RECT 60.912000 5.490000 60.988000 7.110000 ;
 RECT 61.156000 5.490000 61.232000 7.110000 ;
 RECT 60.424000 7.110000 60.500000 8.730000 ;
 RECT 60.668000 7.110000 60.744000 8.730000 ;
 RECT 60.912000 7.110000 60.988000 8.730000 ;
 RECT 61.156000 7.110000 61.232000 8.730000 ;
 RECT 60.424000 8.730000 60.500000 10.350000 ;
 RECT 60.668000 8.730000 60.744000 10.350000 ;
 RECT 60.912000 8.730000 60.988000 10.350000 ;
 RECT 61.156000 8.730000 61.232000 10.350000 ;
 RECT 77.268000 3.870000 77.344000 5.490000 ;
 RECT 77.512000 3.870000 77.588000 5.490000 ;
 RECT 77.756000 3.870000 77.832000 5.490000 ;
 RECT 78.000000 3.870000 78.076000 5.490000 ;
 RECT 60.424000 10.350000 60.500000 11.970000 ;
 RECT 60.668000 10.350000 60.744000 11.970000 ;
 RECT 60.912000 10.350000 60.988000 11.970000 ;
 RECT 61.156000 10.350000 61.232000 11.970000 ;
 RECT 60.424000 11.970000 60.500000 13.590000 ;
 RECT 60.668000 11.970000 60.744000 13.590000 ;
 RECT 60.912000 11.970000 60.988000 13.590000 ;
 RECT 61.156000 11.970000 61.232000 13.590000 ;
 RECT 60.424000 13.590000 60.500000 15.210000 ;
 RECT 60.668000 13.590000 60.744000 15.210000 ;
 RECT 60.912000 13.590000 60.988000 15.210000 ;
 RECT 61.156000 13.590000 61.232000 15.210000 ;
 RECT 60.424000 15.210000 60.500000 16.830000 ;
 RECT 60.668000 15.210000 60.744000 16.830000 ;
 RECT 60.912000 15.210000 60.988000 16.830000 ;
 RECT 61.156000 15.210000 61.232000 16.830000 ;
 RECT 60.424000 16.830000 60.500000 18.450000 ;
 RECT 60.668000 16.830000 60.744000 18.450000 ;
 RECT 60.912000 16.830000 60.988000 18.450000 ;
 RECT 61.156000 16.830000 61.232000 18.450000 ;
 RECT 60.424000 18.450000 60.500000 20.070000 ;
 RECT 60.668000 18.450000 60.744000 20.070000 ;
 RECT 60.912000 18.450000 60.988000 20.070000 ;
 RECT 61.156000 18.450000 61.232000 20.070000 ;
 RECT 60.424000 20.070000 60.500000 21.690000 ;
 RECT 60.668000 20.070000 60.744000 21.690000 ;
 RECT 60.912000 20.070000 60.988000 21.690000 ;
 RECT 61.156000 20.070000 61.232000 21.690000 ;
 RECT 60.424000 21.690000 60.500000 23.310000 ;
 RECT 60.668000 21.690000 60.744000 23.310000 ;
 RECT 60.912000 21.690000 60.988000 23.310000 ;
 RECT 61.156000 21.690000 61.232000 23.310000 ;
 RECT 60.424000 23.310000 60.500000 24.930000 ;
 RECT 60.668000 23.310000 60.744000 24.930000 ;
 RECT 60.912000 23.310000 60.988000 24.930000 ;
 RECT 61.156000 23.310000 61.232000 24.930000 ;
 RECT 60.424000 24.930000 60.500000 26.550000 ;
 RECT 60.668000 24.930000 60.744000 26.550000 ;
 RECT 60.912000 24.930000 60.988000 26.550000 ;
 RECT 61.156000 24.930000 61.232000 26.550000 ;
 RECT 77.268000 5.490000 77.344000 7.110000 ;
 RECT 77.512000 5.490000 77.588000 7.110000 ;
 RECT 77.756000 5.490000 77.832000 7.110000 ;
 RECT 78.000000 5.490000 78.076000 7.110000 ;
 RECT 60.424000 39.150000 60.500000 40.770000 ;
 RECT 60.668000 39.150000 60.744000 40.770000 ;
 RECT 60.912000 39.150000 60.988000 40.770000 ;
 RECT 61.156000 39.150000 61.232000 40.770000 ;
 RECT 60.424000 40.770000 60.500000 42.390000 ;
 RECT 60.668000 40.770000 60.744000 42.390000 ;
 RECT 60.912000 40.770000 60.988000 42.390000 ;
 RECT 61.156000 40.770000 61.232000 42.390000 ;
 RECT 60.424000 42.390000 60.500000 44.010000 ;
 RECT 60.668000 42.390000 60.744000 44.010000 ;
 RECT 60.912000 42.390000 60.988000 44.010000 ;
 RECT 61.156000 42.390000 61.232000 44.010000 ;
 RECT 60.424000 44.010000 60.500000 45.630000 ;
 RECT 60.668000 44.010000 60.744000 45.630000 ;
 RECT 60.912000 44.010000 60.988000 45.630000 ;
 RECT 61.156000 44.010000 61.232000 45.630000 ;
 RECT 60.424000 45.630000 60.500000 47.250000 ;
 RECT 60.668000 45.630000 60.744000 47.250000 ;
 RECT 60.912000 45.630000 60.988000 47.250000 ;
 RECT 61.156000 45.630000 61.232000 47.250000 ;
 RECT 60.424000 47.250000 60.500000 48.870000 ;
 RECT 60.668000 47.250000 60.744000 48.870000 ;
 RECT 60.912000 47.250000 60.988000 48.870000 ;
 RECT 61.156000 47.250000 61.232000 48.870000 ;
 RECT 60.424000 48.870000 60.500000 50.490000 ;
 RECT 60.668000 48.870000 60.744000 50.490000 ;
 RECT 60.912000 48.870000 60.988000 50.490000 ;
 RECT 61.156000 48.870000 61.232000 50.490000 ;
 RECT 60.424000 50.490000 60.500000 52.110000 ;
 RECT 60.668000 50.490000 60.744000 52.110000 ;
 RECT 60.912000 50.490000 60.988000 52.110000 ;
 RECT 61.156000 50.490000 61.232000 52.110000 ;
 RECT 60.424000 52.110000 60.500000 53.730000 ;
 RECT 60.668000 52.110000 60.744000 53.730000 ;
 RECT 60.912000 52.110000 60.988000 53.730000 ;
 RECT 61.156000 52.110000 61.232000 53.730000 ;
 RECT 60.424000 53.730000 60.500000 55.350000 ;
 RECT 60.668000 53.730000 60.744000 55.350000 ;
 RECT 60.912000 53.730000 60.988000 55.350000 ;
 RECT 61.156000 53.730000 61.232000 55.350000 ;
 RECT 77.268000 7.110000 77.344000 8.730000 ;
 RECT 77.512000 7.110000 77.588000 8.730000 ;
 RECT 77.756000 7.110000 77.832000 8.730000 ;
 RECT 78.000000 7.110000 78.076000 8.730000 ;
 RECT 60.424000 55.350000 60.500000 56.970000 ;
 RECT 60.668000 55.350000 60.744000 56.970000 ;
 RECT 60.912000 55.350000 60.988000 56.970000 ;
 RECT 61.156000 55.350000 61.232000 56.970000 ;
 RECT 60.424000 56.970000 60.500000 58.590000 ;
 RECT 60.668000 56.970000 60.744000 58.590000 ;
 RECT 60.912000 56.970000 60.988000 58.590000 ;
 RECT 61.156000 56.970000 61.232000 58.590000 ;
 RECT 60.424000 58.590000 60.500000 60.210000 ;
 RECT 60.668000 58.590000 60.744000 60.210000 ;
 RECT 60.912000 58.590000 60.988000 60.210000 ;
 RECT 61.156000 58.590000 61.232000 60.210000 ;
 RECT 60.424000 60.210000 60.500000 61.830000 ;
 RECT 60.668000 60.210000 60.744000 61.830000 ;
 RECT 60.912000 60.210000 60.988000 61.830000 ;
 RECT 61.156000 60.210000 61.232000 61.830000 ;
 RECT 60.424000 61.830000 60.500000 63.450000 ;
 RECT 60.668000 61.830000 60.744000 63.450000 ;
 RECT 60.912000 61.830000 60.988000 63.450000 ;
 RECT 61.156000 61.830000 61.232000 63.450000 ;
 RECT 60.424000 63.450000 60.500000 65.070000 ;
 RECT 60.668000 63.450000 60.744000 65.070000 ;
 RECT 60.912000 63.450000 60.988000 65.070000 ;
 RECT 61.156000 63.450000 61.232000 65.070000 ;
 RECT 77.268000 8.730000 77.344000 10.350000 ;
 RECT 77.512000 8.730000 77.588000 10.350000 ;
 RECT 77.756000 8.730000 77.832000 10.350000 ;
 RECT 78.000000 8.730000 78.076000 10.350000 ;
 RECT 77.268000 10.350000 77.344000 11.970000 ;
 RECT 77.512000 10.350000 77.588000 11.970000 ;
 RECT 77.756000 10.350000 77.832000 11.970000 ;
 RECT 78.000000 10.350000 78.076000 11.970000 ;
 RECT 77.268000 11.970000 77.344000 13.590000 ;
 RECT 77.512000 11.970000 77.588000 13.590000 ;
 RECT 77.756000 11.970000 77.832000 13.590000 ;
 RECT 78.000000 11.970000 78.076000 13.590000 ;
 END
 END vccperfgt_lv
END ip224uhdlp1p11rf_2048x32m4b2c1s0_t0r0p1d0a1m1h_APACHECELL
END LIBRARY
